VERSION 5.8 ;
BUSBITCHARS "[]" ;
DIVIDERCHAR "/" ;
UNITS
    DATABASE MICRONS 1000 ;
END UNITS

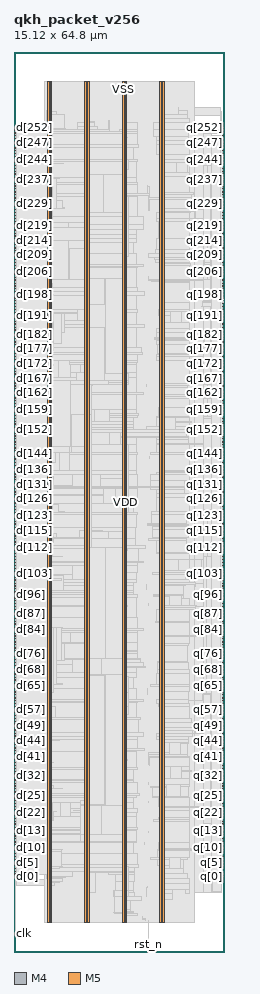
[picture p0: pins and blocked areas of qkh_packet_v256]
MACRO qkh_packet_v256
  FOREIGN qkh_packet_v256 0 0 ;
  CLASS BLOCK ;
  SIZE 15.12 BY 64.8 ;
  PIN clk
    DIRECTION INPUT ;
    USE SIGNAL ;
    PORT
      LAYER M4 ;
        RECT  0.054 1.296 0.138 1.32 ;
    END
    PORT
      LAYER M4 ;
        RECT  0.108 1.296 0.227 1.416 ;
    END
  END clk
  PIN d[0]
    DIRECTION INPUT ;
    USE SIGNAL ;
    PORT
      LAYER M4 ;
        RECT  0.054 5.424 0.138 5.448 ;
    END
  END d[0]
  PIN d[100]
    DIRECTION INPUT ;
    USE SIGNAL ;
    PORT
      LAYER M4 ;
        RECT  0.054 26.544 0.138 26.568 ;
    END
  END d[100]
  PIN d[101]
    DIRECTION INPUT ;
    USE SIGNAL ;
    PORT
      LAYER M4 ;
        RECT  0.054 26.784 0.138 26.808 ;
    END
  END d[101]
  PIN d[102]
    DIRECTION INPUT ;
    USE SIGNAL ;
    PORT
      LAYER M4 ;
        RECT  0.054 26.976 0.138 27 ;
    END
  END d[102]
  PIN d[103]
    DIRECTION INPUT ;
    USE SIGNAL ;
    PORT
      LAYER M4 ;
        RECT  0.054 27.216 0.138 27.24 ;
    END
  END d[103]
  PIN d[104]
    DIRECTION INPUT ;
    USE SIGNAL ;
    PORT
      LAYER M4 ;
        RECT  0.054 27.408 0.138 27.432 ;
    END
  END d[104]
  PIN d[105]
    DIRECTION INPUT ;
    USE SIGNAL ;
    PORT
      LAYER M4 ;
        RECT  0.054 27.6 0.138 27.624 ;
    END
  END d[105]
  PIN d[106]
    DIRECTION INPUT ;
    USE SIGNAL ;
    PORT
      LAYER M4 ;
        RECT  0.054 27.84 0.138 27.864 ;
    END
  END d[106]
  PIN d[107]
    DIRECTION INPUT ;
    USE SIGNAL ;
    PORT
      LAYER M4 ;
        RECT  0.054 28.032 0.138 28.056 ;
    END
  END d[107]
  PIN d[108]
    DIRECTION INPUT ;
    USE SIGNAL ;
    PORT
      LAYER M4 ;
        RECT  0.054 28.272 0.138 28.296 ;
    END
  END d[108]
  PIN d[109]
    DIRECTION INPUT ;
    USE SIGNAL ;
    PORT
      LAYER M4 ;
        RECT  0.054 28.464 0.138 28.488 ;
    END
  END d[109]
  PIN d[10]
    DIRECTION INPUT ;
    USE SIGNAL ;
    PORT
      LAYER M4 ;
        RECT  0.054 7.488 0.138 7.512 ;
    END
  END d[10]
  PIN d[110]
    DIRECTION INPUT ;
    USE SIGNAL ;
    PORT
      LAYER M4 ;
        RECT  0.054 28.704 0.138 28.728 ;
    END
  END d[110]
  PIN d[111]
    DIRECTION INPUT ;
    USE SIGNAL ;
    PORT
      LAYER M4 ;
        RECT  0.054 28.896 0.138 28.92 ;
    END
  END d[111]
  PIN d[112]
    DIRECTION INPUT ;
    USE SIGNAL ;
    PORT
      LAYER M4 ;
        RECT  0.054 29.088 0.138 29.112 ;
    END
  END d[112]
  PIN d[113]
    DIRECTION INPUT ;
    USE SIGNAL ;
    PORT
      LAYER M4 ;
        RECT  0.054 29.328 0.138 29.352 ;
    END
  END d[113]
  PIN d[114]
    DIRECTION INPUT ;
    USE SIGNAL ;
    PORT
      LAYER M4 ;
        RECT  0.054 29.52 0.138 29.544 ;
    END
  END d[114]
  PIN d[115]
    DIRECTION INPUT ;
    USE SIGNAL ;
    PORT
      LAYER M4 ;
        RECT  0.054 29.76 0.138 29.784 ;
    END
  END d[115]
  PIN d[116]
    DIRECTION INPUT ;
    USE SIGNAL ;
    PORT
      LAYER M4 ;
        RECT  0.054 29.952 0.138 29.976 ;
    END
  END d[116]
  PIN d[117]
    DIRECTION INPUT ;
    USE SIGNAL ;
    PORT
      LAYER M4 ;
        RECT  0.054 30.144 0.138 30.168 ;
    END
  END d[117]
  PIN d[118]
    DIRECTION INPUT ;
    USE SIGNAL ;
    PORT
      LAYER M4 ;
        RECT  0.054 30.384 0.138 30.408 ;
    END
  END d[118]
  PIN d[119]
    DIRECTION INPUT ;
    USE SIGNAL ;
    PORT
      LAYER M4 ;
        RECT  0.054 30.576 0.138 30.6 ;
    END
  END d[119]
  PIN d[11]
    DIRECTION INPUT ;
    USE SIGNAL ;
    PORT
      LAYER M4 ;
        RECT  0.054 7.728 0.138 7.752 ;
    END
  END d[11]
  PIN d[120]
    DIRECTION INPUT ;
    USE SIGNAL ;
    PORT
      LAYER M4 ;
        RECT  0.054 30.816 0.138 30.84 ;
    END
  END d[120]
  PIN d[121]
    DIRECTION INPUT ;
    USE SIGNAL ;
    PORT
      LAYER M4 ;
        RECT  0.054 31.008 0.138 31.032 ;
    END
  END d[121]
  PIN d[122]
    DIRECTION INPUT ;
    USE SIGNAL ;
    PORT
      LAYER M4 ;
        RECT  0.054 31.2 0.138 31.224 ;
    END
  END d[122]
  PIN d[123]
    DIRECTION INPUT ;
    USE SIGNAL ;
    PORT
      LAYER M4 ;
        RECT  0.054 31.44 0.138 31.464 ;
    END
  END d[123]
  PIN d[124]
    DIRECTION INPUT ;
    USE SIGNAL ;
    PORT
      LAYER M4 ;
        RECT  0.054 31.632 0.138 31.656 ;
    END
  END d[124]
  PIN d[125]
    DIRECTION INPUT ;
    USE SIGNAL ;
    PORT
      LAYER M4 ;
        RECT  0.054 31.872 0.138 31.896 ;
    END
  END d[125]
  PIN d[126]
    DIRECTION INPUT ;
    USE SIGNAL ;
    PORT
      LAYER M4 ;
        RECT  0.054 32.064 0.138 32.088 ;
    END
  END d[126]
  PIN d[127]
    DIRECTION INPUT ;
    USE SIGNAL ;
    PORT
      LAYER M4 ;
        RECT  0.054 32.304 0.138 32.328 ;
    END
  END d[127]
  PIN d[128]
    DIRECTION INPUT ;
    USE SIGNAL ;
    PORT
      LAYER M4 ;
        RECT  0.054 32.496 0.138 32.52 ;
    END
  END d[128]
  PIN d[129]
    DIRECTION INPUT ;
    USE SIGNAL ;
    PORT
      LAYER M4 ;
        RECT  0.054 32.688 0.138 32.712 ;
    END
  END d[129]
  PIN d[12]
    DIRECTION INPUT ;
    USE SIGNAL ;
    PORT
      LAYER M4 ;
        RECT  0.054 7.92 0.138 7.944 ;
    END
  END d[12]
  PIN d[130]
    DIRECTION INPUT ;
    USE SIGNAL ;
    PORT
      LAYER M4 ;
        RECT  0.054 32.928 0.138 32.952 ;
    END
  END d[130]
  PIN d[131]
    DIRECTION INPUT ;
    USE SIGNAL ;
    PORT
      LAYER M4 ;
        RECT  0.054 33.12 0.138 33.144 ;
    END
  END d[131]
  PIN d[132]
    DIRECTION INPUT ;
    USE SIGNAL ;
    PORT
      LAYER M4 ;
        RECT  0.054 33.36 0.138 33.384 ;
    END
  END d[132]
  PIN d[133]
    DIRECTION INPUT ;
    USE SIGNAL ;
    PORT
      LAYER M4 ;
        RECT  0.054 33.552 0.138 33.576 ;
    END
  END d[133]
  PIN d[134]
    DIRECTION INPUT ;
    USE SIGNAL ;
    PORT
      LAYER M4 ;
        RECT  0.054 33.744 0.138 33.768 ;
    END
  END d[134]
  PIN d[135]
    DIRECTION INPUT ;
    USE SIGNAL ;
    PORT
      LAYER M4 ;
        RECT  0.054 33.984 0.138 34.008 ;
    END
  END d[135]
  PIN d[136]
    DIRECTION INPUT ;
    USE SIGNAL ;
    PORT
      LAYER M4 ;
        RECT  0.054 34.176 0.138 34.2 ;
    END
  END d[136]
  PIN d[137]
    DIRECTION INPUT ;
    USE SIGNAL ;
    PORT
      LAYER M4 ;
        RECT  0.054 34.416 0.138 34.44 ;
    END
  END d[137]
  PIN d[138]
    DIRECTION INPUT ;
    USE SIGNAL ;
    PORT
      LAYER M4 ;
        RECT  0.054 34.608 0.138 34.632 ;
    END
  END d[138]
  PIN d[139]
    DIRECTION INPUT ;
    USE SIGNAL ;
    PORT
      LAYER M4 ;
        RECT  0.054 34.8 0.138 34.824 ;
    END
  END d[139]
  PIN d[13]
    DIRECTION INPUT ;
    USE SIGNAL ;
    PORT
      LAYER M4 ;
        RECT  0.054 8.16 0.138 8.184 ;
    END
  END d[13]
  PIN d[140]
    DIRECTION INPUT ;
    USE SIGNAL ;
    PORT
      LAYER M4 ;
        RECT  0.054 35.04 0.138 35.064 ;
    END
  END d[140]
  PIN d[141]
    DIRECTION INPUT ;
    USE SIGNAL ;
    PORT
      LAYER M4 ;
        RECT  0.054 35.232 0.138 35.256 ;
    END
  END d[141]
  PIN d[142]
    DIRECTION INPUT ;
    USE SIGNAL ;
    PORT
      LAYER M4 ;
        RECT  0.054 35.472 0.138 35.496 ;
    END
  END d[142]
  PIN d[143]
    DIRECTION INPUT ;
    USE SIGNAL ;
    PORT
      LAYER M4 ;
        RECT  0.054 35.664 0.138 35.688 ;
    END
  END d[143]
  PIN d[144]
    DIRECTION INPUT ;
    USE SIGNAL ;
    PORT
      LAYER M4 ;
        RECT  0.054 35.904 0.138 35.928 ;
    END
  END d[144]
  PIN d[145]
    DIRECTION INPUT ;
    USE SIGNAL ;
    PORT
      LAYER M4 ;
        RECT  0.054 36.096 0.138 36.12 ;
    END
  END d[145]
  PIN d[146]
    DIRECTION INPUT ;
    USE SIGNAL ;
    PORT
      LAYER M4 ;
        RECT  0.054 36.288 0.138 36.312 ;
    END
  END d[146]
  PIN d[147]
    DIRECTION INPUT ;
    USE SIGNAL ;
    PORT
      LAYER M4 ;
        RECT  0.054 36.528 0.138 36.552 ;
    END
  END d[147]
  PIN d[148]
    DIRECTION INPUT ;
    USE SIGNAL ;
    PORT
      LAYER M4 ;
        RECT  0.054 36.72 0.138 36.744 ;
    END
  END d[148]
  PIN d[149]
    DIRECTION INPUT ;
    USE SIGNAL ;
    PORT
      LAYER M4 ;
        RECT  0.054 36.96 0.138 36.984 ;
    END
  END d[149]
  PIN d[14]
    DIRECTION INPUT ;
    USE SIGNAL ;
    PORT
      LAYER M4 ;
        RECT  0.054 8.352 0.138 8.376 ;
    END
  END d[14]
  PIN d[150]
    DIRECTION INPUT ;
    USE SIGNAL ;
    PORT
      LAYER M4 ;
        RECT  0.054 37.152 0.138 37.176 ;
    END
  END d[150]
  PIN d[151]
    DIRECTION INPUT ;
    USE SIGNAL ;
    PORT
      LAYER M4 ;
        RECT  0.054 37.344 0.138 37.368 ;
    END
  END d[151]
  PIN d[152]
    DIRECTION INPUT ;
    USE SIGNAL ;
    PORT
      LAYER M4 ;
        RECT  0.054 37.584 0.138 37.608 ;
    END
  END d[152]
  PIN d[153]
    DIRECTION INPUT ;
    USE SIGNAL ;
    PORT
      LAYER M4 ;
        RECT  0.054 37.776 0.138 37.8 ;
    END
  END d[153]
  PIN d[154]
    DIRECTION INPUT ;
    USE SIGNAL ;
    PORT
      LAYER M4 ;
        RECT  0.054 38.016 0.138 38.04 ;
    END
  END d[154]
  PIN d[155]
    DIRECTION INPUT ;
    USE SIGNAL ;
    PORT
      LAYER M4 ;
        RECT  0.054 38.208 0.138 38.232 ;
    END
  END d[155]
  PIN d[156]
    DIRECTION INPUT ;
    USE SIGNAL ;
    PORT
      LAYER M4 ;
        RECT  0.054 38.4 0.138 38.424 ;
    END
  END d[156]
  PIN d[157]
    DIRECTION INPUT ;
    USE SIGNAL ;
    PORT
      LAYER M4 ;
        RECT  0.054 38.64 0.138 38.664 ;
    END
  END d[157]
  PIN d[158]
    DIRECTION INPUT ;
    USE SIGNAL ;
    PORT
      LAYER M4 ;
        RECT  0.054 38.832 0.138 38.856 ;
    END
  END d[158]
  PIN d[159]
    DIRECTION INPUT ;
    USE SIGNAL ;
    PORT
      LAYER M4 ;
        RECT  0.054 39.072 0.138 39.096 ;
    END
  END d[159]
  PIN d[15]
    DIRECTION INPUT ;
    USE SIGNAL ;
    PORT
      LAYER M4 ;
        RECT  0.054 8.544 0.138 8.568 ;
    END
  END d[15]
  PIN d[160]
    DIRECTION INPUT ;
    USE SIGNAL ;
    PORT
      LAYER M4 ;
        RECT  0.054 39.264 0.138 39.288 ;
    END
  END d[160]
  PIN d[161]
    DIRECTION INPUT ;
    USE SIGNAL ;
    PORT
      LAYER M4 ;
        RECT  0.054 39.504 0.138 39.528 ;
    END
  END d[161]
  PIN d[162]
    DIRECTION INPUT ;
    USE SIGNAL ;
    PORT
      LAYER M4 ;
        RECT  0.054 39.696 0.138 39.72 ;
    END
  END d[162]
  PIN d[163]
    DIRECTION INPUT ;
    USE SIGNAL ;
    PORT
      LAYER M4 ;
        RECT  0.054 39.888 0.138 39.912 ;
    END
  END d[163]
  PIN d[164]
    DIRECTION INPUT ;
    USE SIGNAL ;
    PORT
      LAYER M4 ;
        RECT  0.054 40.128 0.138 40.152 ;
    END
  END d[164]
  PIN d[165]
    DIRECTION INPUT ;
    USE SIGNAL ;
    PORT
      LAYER M4 ;
        RECT  0.054 40.32 0.138 40.344 ;
    END
  END d[165]
  PIN d[166]
    DIRECTION INPUT ;
    USE SIGNAL ;
    PORT
      LAYER M4 ;
        RECT  0.054 40.56 0.138 40.584 ;
    END
  END d[166]
  PIN d[167]
    DIRECTION INPUT ;
    USE SIGNAL ;
    PORT
      LAYER M4 ;
        RECT  0.054 40.752 0.138 40.776 ;
    END
  END d[167]
  PIN d[168]
    DIRECTION INPUT ;
    USE SIGNAL ;
    PORT
      LAYER M4 ;
        RECT  0.054 40.944 0.138 40.968 ;
    END
  END d[168]
  PIN d[169]
    DIRECTION INPUT ;
    USE SIGNAL ;
    PORT
      LAYER M4 ;
        RECT  0.054 41.184 0.138 41.208 ;
    END
  END d[169]
  PIN d[16]
    DIRECTION INPUT ;
    USE SIGNAL ;
    PORT
      LAYER M4 ;
        RECT  0.054 8.784 0.138 8.808 ;
    END
  END d[16]
  PIN d[170]
    DIRECTION INPUT ;
    USE SIGNAL ;
    PORT
      LAYER M4 ;
        RECT  0.054 41.376 0.138 41.4 ;
    END
  END d[170]
  PIN d[171]
    DIRECTION INPUT ;
    USE SIGNAL ;
    PORT
      LAYER M4 ;
        RECT  0.054 41.616 0.138 41.64 ;
    END
  END d[171]
  PIN d[172]
    DIRECTION INPUT ;
    USE SIGNAL ;
    PORT
      LAYER M4 ;
        RECT  0.054 41.808 0.138 41.832 ;
    END
  END d[172]
  PIN d[173]
    DIRECTION INPUT ;
    USE SIGNAL ;
    PORT
      LAYER M4 ;
        RECT  0.054 42 0.138 42.024 ;
    END
  END d[173]
  PIN d[174]
    DIRECTION INPUT ;
    USE SIGNAL ;
    PORT
      LAYER M4 ;
        RECT  0.054 42.24 0.138 42.264 ;
    END
  END d[174]
  PIN d[175]
    DIRECTION INPUT ;
    USE SIGNAL ;
    PORT
      LAYER M4 ;
        RECT  0.054 42.432 0.138 42.456 ;
    END
  END d[175]
  PIN d[176]
    DIRECTION INPUT ;
    USE SIGNAL ;
    PORT
      LAYER M4 ;
        RECT  0.054 42.672 0.138 42.696 ;
    END
  END d[176]
  PIN d[177]
    DIRECTION INPUT ;
    USE SIGNAL ;
    PORT
      LAYER M4 ;
        RECT  0.054 42.864 0.138 42.888 ;
    END
  END d[177]
  PIN d[178]
    DIRECTION INPUT ;
    USE SIGNAL ;
    PORT
      LAYER M4 ;
        RECT  0.054 43.104 0.138 43.128 ;
    END
  END d[178]
  PIN d[179]
    DIRECTION INPUT ;
    USE SIGNAL ;
    PORT
      LAYER M4 ;
        RECT  0.054 43.296 0.138 43.32 ;
    END
  END d[179]
  PIN d[17]
    DIRECTION INPUT ;
    USE SIGNAL ;
    PORT
      LAYER M4 ;
        RECT  0.054 8.976 0.138 9 ;
    END
  END d[17]
  PIN d[180]
    DIRECTION INPUT ;
    USE SIGNAL ;
    PORT
      LAYER M4 ;
        RECT  0.054 43.488 0.138 43.512 ;
    END
  END d[180]
  PIN d[181]
    DIRECTION INPUT ;
    USE SIGNAL ;
    PORT
      LAYER M4 ;
        RECT  0.054 43.728 0.138 43.752 ;
    END
  END d[181]
  PIN d[182]
    DIRECTION INPUT ;
    USE SIGNAL ;
    PORT
      LAYER M4 ;
        RECT  0.054 43.92 0.138 43.944 ;
    END
  END d[182]
  PIN d[183]
    DIRECTION INPUT ;
    USE SIGNAL ;
    PORT
      LAYER M4 ;
        RECT  0.054 44.16 0.138 44.184 ;
    END
  END d[183]
  PIN d[184]
    DIRECTION INPUT ;
    USE SIGNAL ;
    PORT
      LAYER M4 ;
        RECT  0.054 44.352 0.138 44.376 ;
    END
  END d[184]
  PIN d[185]
    DIRECTION INPUT ;
    USE SIGNAL ;
    PORT
      LAYER M4 ;
        RECT  0.054 44.544 0.138 44.568 ;
    END
  END d[185]
  PIN d[186]
    DIRECTION INPUT ;
    USE SIGNAL ;
    PORT
      LAYER M4 ;
        RECT  0.054 44.784 0.138 44.808 ;
    END
  END d[186]
  PIN d[187]
    DIRECTION INPUT ;
    USE SIGNAL ;
    PORT
      LAYER M4 ;
        RECT  0.054 44.976 0.138 45 ;
    END
  END d[187]
  PIN d[188]
    DIRECTION INPUT ;
    USE SIGNAL ;
    PORT
      LAYER M4 ;
        RECT  0.054 45.216 0.138 45.24 ;
    END
  END d[188]
  PIN d[189]
    DIRECTION INPUT ;
    USE SIGNAL ;
    PORT
      LAYER M4 ;
        RECT  0.054 45.408 0.138 45.432 ;
    END
  END d[189]
  PIN d[18]
    DIRECTION INPUT ;
    USE SIGNAL ;
    PORT
      LAYER M4 ;
        RECT  0.054 9.216 0.138 9.24 ;
    END
  END d[18]
  PIN d[190]
    DIRECTION INPUT ;
    USE SIGNAL ;
    PORT
      LAYER M4 ;
        RECT  0.054 45.6 0.138 45.624 ;
    END
  END d[190]
  PIN d[191]
    DIRECTION INPUT ;
    USE SIGNAL ;
    PORT
      LAYER M4 ;
        RECT  0.054 45.84 0.138 45.864 ;
    END
  END d[191]
  PIN d[192]
    DIRECTION INPUT ;
    USE SIGNAL ;
    PORT
      LAYER M4 ;
        RECT  0.054 46.032 0.138 46.056 ;
    END
  END d[192]
  PIN d[193]
    DIRECTION INPUT ;
    USE SIGNAL ;
    PORT
      LAYER M4 ;
        RECT  0.054 46.272 0.138 46.296 ;
    END
  END d[193]
  PIN d[194]
    DIRECTION INPUT ;
    USE SIGNAL ;
    PORT
      LAYER M4 ;
        RECT  0.054 46.464 0.138 46.488 ;
    END
  END d[194]
  PIN d[195]
    DIRECTION INPUT ;
    USE SIGNAL ;
    PORT
      LAYER M4 ;
        RECT  0.054 46.704 0.138 46.728 ;
    END
  END d[195]
  PIN d[196]
    DIRECTION INPUT ;
    USE SIGNAL ;
    PORT
      LAYER M4 ;
        RECT  0.054 46.896 0.138 46.92 ;
    END
  END d[196]
  PIN d[197]
    DIRECTION INPUT ;
    USE SIGNAL ;
    PORT
      LAYER M4 ;
        RECT  0.054 47.088 0.138 47.112 ;
    END
  END d[197]
  PIN d[198]
    DIRECTION INPUT ;
    USE SIGNAL ;
    PORT
      LAYER M4 ;
        RECT  0.054 47.328 0.138 47.352 ;
    END
  END d[198]
  PIN d[199]
    DIRECTION INPUT ;
    USE SIGNAL ;
    PORT
      LAYER M4 ;
        RECT  0.054 47.52 0.138 47.544 ;
    END
  END d[199]
  PIN d[19]
    DIRECTION INPUT ;
    USE SIGNAL ;
    PORT
      LAYER M4 ;
        RECT  0.054 9.408 0.138 9.432 ;
    END
  END d[19]
  PIN d[1]
    DIRECTION INPUT ;
    USE SIGNAL ;
    PORT
      LAYER M4 ;
        RECT  0.054 5.616 0.138 5.64 ;
    END
  END d[1]
  PIN d[200]
    DIRECTION INPUT ;
    USE SIGNAL ;
    PORT
      LAYER M4 ;
        RECT  0.054 47.76 0.138 47.784 ;
    END
  END d[200]
  PIN d[201]
    DIRECTION INPUT ;
    USE SIGNAL ;
    PORT
      LAYER M4 ;
        RECT  0.054 47.952 0.138 47.976 ;
    END
  END d[201]
  PIN d[202]
    DIRECTION INPUT ;
    USE SIGNAL ;
    PORT
      LAYER M4 ;
        RECT  0.054 48.144 0.138 48.168 ;
    END
  END d[202]
  PIN d[203]
    DIRECTION INPUT ;
    USE SIGNAL ;
    PORT
      LAYER M4 ;
        RECT  0.054 48.384 0.138 48.408 ;
    END
  END d[203]
  PIN d[204]
    DIRECTION INPUT ;
    USE SIGNAL ;
    PORT
      LAYER M4 ;
        RECT  0.054 48.576 0.138 48.6 ;
    END
  END d[204]
  PIN d[205]
    DIRECTION INPUT ;
    USE SIGNAL ;
    PORT
      LAYER M4 ;
        RECT  0.054 48.816 0.138 48.84 ;
    END
  END d[205]
  PIN d[206]
    DIRECTION INPUT ;
    USE SIGNAL ;
    PORT
      LAYER M4 ;
        RECT  0.054 49.008 0.138 49.032 ;
    END
  END d[206]
  PIN d[207]
    DIRECTION INPUT ;
    USE SIGNAL ;
    PORT
      LAYER M4 ;
        RECT  0.054 49.2 0.138 49.224 ;
    END
  END d[207]
  PIN d[208]
    DIRECTION INPUT ;
    USE SIGNAL ;
    PORT
      LAYER M4 ;
        RECT  0.054 49.44 0.138 49.464 ;
    END
  END d[208]
  PIN d[209]
    DIRECTION INPUT ;
    USE SIGNAL ;
    PORT
      LAYER M4 ;
        RECT  0.054 49.632 0.138 49.656 ;
    END
  END d[209]
  PIN d[20]
    DIRECTION INPUT ;
    USE SIGNAL ;
    PORT
      LAYER M4 ;
        RECT  0.054 9.6 0.138 9.624 ;
    END
  END d[20]
  PIN d[210]
    DIRECTION INPUT ;
    USE SIGNAL ;
    PORT
      LAYER M4 ;
        RECT  0.054 49.872 0.138 49.896 ;
    END
  END d[210]
  PIN d[211]
    DIRECTION INPUT ;
    USE SIGNAL ;
    PORT
      LAYER M4 ;
        RECT  0.054 50.064 0.138 50.088 ;
    END
  END d[211]
  PIN d[212]
    DIRECTION INPUT ;
    USE SIGNAL ;
    PORT
      LAYER M4 ;
        RECT  0.054 50.304 0.138 50.328 ;
    END
  END d[212]
  PIN d[213]
    DIRECTION INPUT ;
    USE SIGNAL ;
    PORT
      LAYER M4 ;
        RECT  0.054 50.496 0.138 50.52 ;
    END
  END d[213]
  PIN d[214]
    DIRECTION INPUT ;
    USE SIGNAL ;
    PORT
      LAYER M4 ;
        RECT  0.054 50.688 0.138 50.712 ;
    END
  END d[214]
  PIN d[215]
    DIRECTION INPUT ;
    USE SIGNAL ;
    PORT
      LAYER M4 ;
        RECT  0.054 50.928 0.138 50.952 ;
    END
  END d[215]
  PIN d[216]
    DIRECTION INPUT ;
    USE SIGNAL ;
    PORT
      LAYER M4 ;
        RECT  0.054 51.12 0.138 51.144 ;
    END
  END d[216]
  PIN d[217]
    DIRECTION INPUT ;
    USE SIGNAL ;
    PORT
      LAYER M4 ;
        RECT  0.054 51.36 0.138 51.384 ;
    END
  END d[217]
  PIN d[218]
    DIRECTION INPUT ;
    USE SIGNAL ;
    PORT
      LAYER M4 ;
        RECT  0.054 51.552 0.138 51.576 ;
    END
  END d[218]
  PIN d[219]
    DIRECTION INPUT ;
    USE SIGNAL ;
    PORT
      LAYER M4 ;
        RECT  0.054 51.744 0.138 51.768 ;
    END
  END d[219]
  PIN d[21]
    DIRECTION INPUT ;
    USE SIGNAL ;
    PORT
      LAYER M4 ;
        RECT  0.054 9.84 0.138 9.864 ;
    END
  END d[21]
  PIN d[220]
    DIRECTION INPUT ;
    USE SIGNAL ;
    PORT
      LAYER M4 ;
        RECT  0.054 51.984 0.138 52.008 ;
    END
  END d[220]
  PIN d[221]
    DIRECTION INPUT ;
    USE SIGNAL ;
    PORT
      LAYER M4 ;
        RECT  0.054 52.176 0.138 52.2 ;
    END
  END d[221]
  PIN d[222]
    DIRECTION INPUT ;
    USE SIGNAL ;
    PORT
      LAYER M4 ;
        RECT  0.054 52.416 0.138 52.44 ;
    END
  END d[222]
  PIN d[223]
    DIRECTION INPUT ;
    USE SIGNAL ;
    PORT
      LAYER M4 ;
        RECT  0.054 52.608 0.138 52.632 ;
    END
  END d[223]
  PIN d[224]
    DIRECTION INPUT ;
    USE SIGNAL ;
    PORT
      LAYER M4 ;
        RECT  0.054 52.8 0.138 52.824 ;
    END
  END d[224]
  PIN d[225]
    DIRECTION INPUT ;
    USE SIGNAL ;
    PORT
      LAYER M4 ;
        RECT  0.054 53.04 0.138 53.064 ;
    END
  END d[225]
  PIN d[226]
    DIRECTION INPUT ;
    USE SIGNAL ;
    PORT
      LAYER M4 ;
        RECT  0.054 53.232 0.138 53.256 ;
    END
  END d[226]
  PIN d[227]
    DIRECTION INPUT ;
    USE SIGNAL ;
    PORT
      LAYER M4 ;
        RECT  0.054 53.472 0.138 53.496 ;
    END
  END d[227]
  PIN d[228]
    DIRECTION INPUT ;
    USE SIGNAL ;
    PORT
      LAYER M4 ;
        RECT  0.054 53.664 0.138 53.688 ;
    END
  END d[228]
  PIN d[229]
    DIRECTION INPUT ;
    USE SIGNAL ;
    PORT
      LAYER M4 ;
        RECT  0.054 53.904 0.138 53.928 ;
    END
  END d[229]
  PIN d[22]
    DIRECTION INPUT ;
    USE SIGNAL ;
    PORT
      LAYER M4 ;
        RECT  0.054 10.032 0.138 10.056 ;
    END
  END d[22]
  PIN d[230]
    DIRECTION INPUT ;
    USE SIGNAL ;
    PORT
      LAYER M4 ;
        RECT  0.054 54.096 0.138 54.12 ;
    END
  END d[230]
  PIN d[231]
    DIRECTION INPUT ;
    USE SIGNAL ;
    PORT
      LAYER M4 ;
        RECT  0.054 54.288 0.138 54.312 ;
    END
  END d[231]
  PIN d[232]
    DIRECTION INPUT ;
    USE SIGNAL ;
    PORT
      LAYER M4 ;
        RECT  0.054 54.528 0.138 54.552 ;
    END
  END d[232]
  PIN d[233]
    DIRECTION INPUT ;
    USE SIGNAL ;
    PORT
      LAYER M4 ;
        RECT  0.054 54.72 0.138 54.744 ;
    END
  END d[233]
  PIN d[234]
    DIRECTION INPUT ;
    USE SIGNAL ;
    PORT
      LAYER M4 ;
        RECT  0.054 54.96 0.138 54.984 ;
    END
  END d[234]
  PIN d[235]
    DIRECTION INPUT ;
    USE SIGNAL ;
    PORT
      LAYER M4 ;
        RECT  0.054 55.152 0.138 55.176 ;
    END
  END d[235]
  PIN d[236]
    DIRECTION INPUT ;
    USE SIGNAL ;
    PORT
      LAYER M4 ;
        RECT  0.054 55.344 0.138 55.368 ;
    END
  END d[236]
  PIN d[237]
    DIRECTION INPUT ;
    USE SIGNAL ;
    PORT
      LAYER M4 ;
        RECT  0.054 55.584 0.138 55.608 ;
    END
  END d[237]
  PIN d[238]
    DIRECTION INPUT ;
    USE SIGNAL ;
    PORT
      LAYER M4 ;
        RECT  0.054 55.776 0.138 55.8 ;
    END
  END d[238]
  PIN d[239]
    DIRECTION INPUT ;
    USE SIGNAL ;
    PORT
      LAYER M4 ;
        RECT  0.054 56.016 0.138 56.04 ;
    END
  END d[239]
  PIN d[23]
    DIRECTION INPUT ;
    USE SIGNAL ;
    PORT
      LAYER M4 ;
        RECT  0.054 10.272 0.138 10.296 ;
    END
  END d[23]
  PIN d[240]
    DIRECTION INPUT ;
    USE SIGNAL ;
    PORT
      LAYER M4 ;
        RECT  0.054 56.208 0.138 56.232 ;
    END
  END d[240]
  PIN d[241]
    DIRECTION INPUT ;
    USE SIGNAL ;
    PORT
      LAYER M4 ;
        RECT  0.054 56.4 0.138 56.424 ;
    END
  END d[241]
  PIN d[242]
    DIRECTION INPUT ;
    USE SIGNAL ;
    PORT
      LAYER M4 ;
        RECT  0.054 56.64 0.138 56.664 ;
    END
  END d[242]
  PIN d[243]
    DIRECTION INPUT ;
    USE SIGNAL ;
    PORT
      LAYER M4 ;
        RECT  0.054 56.832 0.138 56.856 ;
    END
  END d[243]
  PIN d[244]
    DIRECTION INPUT ;
    USE SIGNAL ;
    PORT
      LAYER M4 ;
        RECT  0.054 57.072 0.138 57.096 ;
    END
  END d[244]
  PIN d[245]
    DIRECTION INPUT ;
    USE SIGNAL ;
    PORT
      LAYER M4 ;
        RECT  0.054 57.264 0.138 57.288 ;
    END
  END d[245]
  PIN d[246]
    DIRECTION INPUT ;
    USE SIGNAL ;
    PORT
      LAYER M4 ;
        RECT  0.054 57.504 0.138 57.528 ;
    END
  END d[246]
  PIN d[247]
    DIRECTION INPUT ;
    USE SIGNAL ;
    PORT
      LAYER M4 ;
        RECT  0.054 57.696 0.138 57.72 ;
    END
  END d[247]
  PIN d[248]
    DIRECTION INPUT ;
    USE SIGNAL ;
    PORT
      LAYER M4 ;
        RECT  0.054 57.888 0.138 57.912 ;
    END
  END d[248]
  PIN d[249]
    DIRECTION INPUT ;
    USE SIGNAL ;
    PORT
      LAYER M4 ;
        RECT  0.054 58.128 0.138 58.152 ;
    END
  END d[249]
  PIN d[24]
    DIRECTION INPUT ;
    USE SIGNAL ;
    PORT
      LAYER M4 ;
        RECT  0.054 10.464 0.138 10.488 ;
    END
  END d[24]
  PIN d[250]
    DIRECTION INPUT ;
    USE SIGNAL ;
    PORT
      LAYER M4 ;
        RECT  0.054 58.32 0.138 58.344 ;
    END
  END d[250]
  PIN d[251]
    DIRECTION INPUT ;
    USE SIGNAL ;
    PORT
      LAYER M4 ;
        RECT  0.054 58.56 0.138 58.584 ;
    END
  END d[251]
  PIN d[252]
    DIRECTION INPUT ;
    USE SIGNAL ;
    PORT
      LAYER M4 ;
        RECT  0.054 58.752 0.138 58.776 ;
    END
  END d[252]
  PIN d[253]
    DIRECTION INPUT ;
    USE SIGNAL ;
    PORT
      LAYER M4 ;
        RECT  0.054 58.944 0.138 58.968 ;
    END
  END d[253]
  PIN d[254]
    DIRECTION INPUT ;
    USE SIGNAL ;
    PORT
      LAYER M4 ;
        RECT  0.054 59.184 0.138 59.208 ;
    END
  END d[254]
  PIN d[255]
    DIRECTION INPUT ;
    USE SIGNAL ;
    PORT
      LAYER M4 ;
        RECT  0.054 59.376 0.138 59.4 ;
    END
  END d[255]
  PIN d[25]
    DIRECTION INPUT ;
    USE SIGNAL ;
    PORT
      LAYER M4 ;
        RECT  0.054 10.704 0.138 10.728 ;
    END
  END d[25]
  PIN d[26]
    DIRECTION INPUT ;
    USE SIGNAL ;
    PORT
      LAYER M4 ;
        RECT  0.054 10.896 0.138 10.92 ;
    END
  END d[26]
  PIN d[27]
    DIRECTION INPUT ;
    USE SIGNAL ;
    PORT
      LAYER M4 ;
        RECT  0.054 11.088 0.138 11.112 ;
    END
  END d[27]
  PIN d[28]
    DIRECTION INPUT ;
    USE SIGNAL ;
    PORT
      LAYER M4 ;
        RECT  0.054 11.328 0.138 11.352 ;
    END
  END d[28]
  PIN d[29]
    DIRECTION INPUT ;
    USE SIGNAL ;
    PORT
      LAYER M4 ;
        RECT  0.054 11.52 0.138 11.544 ;
    END
  END d[29]
  PIN d[2]
    DIRECTION INPUT ;
    USE SIGNAL ;
    PORT
      LAYER M4 ;
        RECT  0.054 5.808 0.138 5.832 ;
    END
  END d[2]
  PIN d[30]
    DIRECTION INPUT ;
    USE SIGNAL ;
    PORT
      LAYER M4 ;
        RECT  0.054 11.76 0.138 11.784 ;
    END
  END d[30]
  PIN d[31]
    DIRECTION INPUT ;
    USE SIGNAL ;
    PORT
      LAYER M4 ;
        RECT  0.054 11.952 0.138 11.976 ;
    END
  END d[31]
  PIN d[32]
    DIRECTION INPUT ;
    USE SIGNAL ;
    PORT
      LAYER M4 ;
        RECT  0.054 12.144 0.138 12.168 ;
    END
  END d[32]
  PIN d[33]
    DIRECTION INPUT ;
    USE SIGNAL ;
    PORT
      LAYER M4 ;
        RECT  0.054 12.384 0.138 12.408 ;
    END
  END d[33]
  PIN d[34]
    DIRECTION INPUT ;
    USE SIGNAL ;
    PORT
      LAYER M4 ;
        RECT  0.054 12.576 0.138 12.6 ;
    END
  END d[34]
  PIN d[35]
    DIRECTION INPUT ;
    USE SIGNAL ;
    PORT
      LAYER M4 ;
        RECT  0.054 12.816 0.138 12.84 ;
    END
  END d[35]
  PIN d[36]
    DIRECTION INPUT ;
    USE SIGNAL ;
    PORT
      LAYER M4 ;
        RECT  0.054 13.008 0.138 13.032 ;
    END
  END d[36]
  PIN d[37]
    DIRECTION INPUT ;
    USE SIGNAL ;
    PORT
      LAYER M4 ;
        RECT  0.054 13.2 0.138 13.224 ;
    END
  END d[37]
  PIN d[38]
    DIRECTION INPUT ;
    USE SIGNAL ;
    PORT
      LAYER M4 ;
        RECT  0.054 13.44 0.138 13.464 ;
    END
  END d[38]
  PIN d[39]
    DIRECTION INPUT ;
    USE SIGNAL ;
    PORT
      LAYER M4 ;
        RECT  0.054 13.632 0.138 13.656 ;
    END
  END d[39]
  PIN d[3]
    DIRECTION INPUT ;
    USE SIGNAL ;
    PORT
      LAYER M4 ;
        RECT  0.054 6 0.138 6.024 ;
    END
  END d[3]
  PIN d[40]
    DIRECTION INPUT ;
    USE SIGNAL ;
    PORT
      LAYER M4 ;
        RECT  0.054 13.872 0.138 13.896 ;
    END
  END d[40]
  PIN d[41]
    DIRECTION INPUT ;
    USE SIGNAL ;
    PORT
      LAYER M4 ;
        RECT  0.054 14.064 0.138 14.088 ;
    END
  END d[41]
  PIN d[42]
    DIRECTION INPUT ;
    USE SIGNAL ;
    PORT
      LAYER M4 ;
        RECT  0.054 14.304 0.138 14.328 ;
    END
  END d[42]
  PIN d[43]
    DIRECTION INPUT ;
    USE SIGNAL ;
    PORT
      LAYER M4 ;
        RECT  0.054 14.496 0.138 14.52 ;
    END
  END d[43]
  PIN d[44]
    DIRECTION INPUT ;
    USE SIGNAL ;
    PORT
      LAYER M4 ;
        RECT  0.054 14.688 0.138 14.712 ;
    END
  END d[44]
  PIN d[45]
    DIRECTION INPUT ;
    USE SIGNAL ;
    PORT
      LAYER M4 ;
        RECT  0.054 14.928 0.138 14.952 ;
    END
  END d[45]
  PIN d[46]
    DIRECTION INPUT ;
    USE SIGNAL ;
    PORT
      LAYER M4 ;
        RECT  0.054 15.12 0.138 15.144 ;
    END
  END d[46]
  PIN d[47]
    DIRECTION INPUT ;
    USE SIGNAL ;
    PORT
      LAYER M4 ;
        RECT  0.054 15.36 0.138 15.384 ;
    END
  END d[47]
  PIN d[48]
    DIRECTION INPUT ;
    USE SIGNAL ;
    PORT
      LAYER M4 ;
        RECT  0.054 15.552 0.138 15.576 ;
    END
  END d[48]
  PIN d[49]
    DIRECTION INPUT ;
    USE SIGNAL ;
    PORT
      LAYER M4 ;
        RECT  0.054 15.744 0.138 15.768 ;
    END
  END d[49]
  PIN d[4]
    DIRECTION INPUT ;
    USE SIGNAL ;
    PORT
      LAYER M4 ;
        RECT  0.054 6.24 0.138 6.264 ;
    END
  END d[4]
  PIN d[50]
    DIRECTION INPUT ;
    USE SIGNAL ;
    PORT
      LAYER M4 ;
        RECT  0.054 15.984 0.138 16.008 ;
    END
  END d[50]
  PIN d[51]
    DIRECTION INPUT ;
    USE SIGNAL ;
    PORT
      LAYER M4 ;
        RECT  0.054 16.176 0.138 16.2 ;
    END
  END d[51]
  PIN d[52]
    DIRECTION INPUT ;
    USE SIGNAL ;
    PORT
      LAYER M4 ;
        RECT  0.054 16.416 0.138 16.44 ;
    END
  END d[52]
  PIN d[53]
    DIRECTION INPUT ;
    USE SIGNAL ;
    PORT
      LAYER M4 ;
        RECT  0.054 16.608 0.138 16.632 ;
    END
  END d[53]
  PIN d[54]
    DIRECTION INPUT ;
    USE SIGNAL ;
    PORT
      LAYER M4 ;
        RECT  0.054 16.8 0.138 16.824 ;
    END
  END d[54]
  PIN d[55]
    DIRECTION INPUT ;
    USE SIGNAL ;
    PORT
      LAYER M4 ;
        RECT  0.054 17.04 0.138 17.064 ;
    END
  END d[55]
  PIN d[56]
    DIRECTION INPUT ;
    USE SIGNAL ;
    PORT
      LAYER M4 ;
        RECT  0.054 17.232 0.138 17.256 ;
    END
  END d[56]
  PIN d[57]
    DIRECTION INPUT ;
    USE SIGNAL ;
    PORT
      LAYER M4 ;
        RECT  0.054 17.472 0.138 17.496 ;
    END
  END d[57]
  PIN d[58]
    DIRECTION INPUT ;
    USE SIGNAL ;
    PORT
      LAYER M4 ;
        RECT  0.054 17.664 0.138 17.688 ;
    END
  END d[58]
  PIN d[59]
    DIRECTION INPUT ;
    USE SIGNAL ;
    PORT
      LAYER M4 ;
        RECT  0.054 17.904 0.138 17.928 ;
    END
  END d[59]
  PIN d[5]
    DIRECTION INPUT ;
    USE SIGNAL ;
    PORT
      LAYER M4 ;
        RECT  0.054 6.432 0.138 6.456 ;
    END
  END d[5]
  PIN d[60]
    DIRECTION INPUT ;
    USE SIGNAL ;
    PORT
      LAYER M4 ;
        RECT  0.054 18.096 0.138 18.12 ;
    END
  END d[60]
  PIN d[61]
    DIRECTION INPUT ;
    USE SIGNAL ;
    PORT
      LAYER M4 ;
        RECT  0.054 18.288 0.138 18.312 ;
    END
  END d[61]
  PIN d[62]
    DIRECTION INPUT ;
    USE SIGNAL ;
    PORT
      LAYER M4 ;
        RECT  0.054 18.528 0.138 18.552 ;
    END
  END d[62]
  PIN d[63]
    DIRECTION INPUT ;
    USE SIGNAL ;
    PORT
      LAYER M4 ;
        RECT  0.054 18.72 0.138 18.744 ;
    END
  END d[63]
  PIN d[64]
    DIRECTION INPUT ;
    USE SIGNAL ;
    PORT
      LAYER M4 ;
        RECT  0.054 18.96 0.138 18.984 ;
    END
  END d[64]
  PIN d[65]
    DIRECTION INPUT ;
    USE SIGNAL ;
    PORT
      LAYER M4 ;
        RECT  0.054 19.152 0.138 19.176 ;
    END
  END d[65]
  PIN d[66]
    DIRECTION INPUT ;
    USE SIGNAL ;
    PORT
      LAYER M4 ;
        RECT  0.054 19.344 0.138 19.368 ;
    END
  END d[66]
  PIN d[67]
    DIRECTION INPUT ;
    USE SIGNAL ;
    PORT
      LAYER M4 ;
        RECT  0.054 19.584 0.138 19.608 ;
    END
  END d[67]
  PIN d[68]
    DIRECTION INPUT ;
    USE SIGNAL ;
    PORT
      LAYER M4 ;
        RECT  0.054 19.776 0.138 19.8 ;
    END
  END d[68]
  PIN d[69]
    DIRECTION INPUT ;
    USE SIGNAL ;
    PORT
      LAYER M4 ;
        RECT  0.054 20.016 0.138 20.04 ;
    END
  END d[69]
  PIN d[6]
    DIRECTION INPUT ;
    USE SIGNAL ;
    PORT
      LAYER M4 ;
        RECT  0.054 6.672 0.138 6.696 ;
    END
  END d[6]
  PIN d[70]
    DIRECTION INPUT ;
    USE SIGNAL ;
    PORT
      LAYER M4 ;
        RECT  0.054 20.208 0.138 20.232 ;
    END
  END d[70]
  PIN d[71]
    DIRECTION INPUT ;
    USE SIGNAL ;
    PORT
      LAYER M4 ;
        RECT  0.054 20.4 0.138 20.424 ;
    END
  END d[71]
  PIN d[72]
    DIRECTION INPUT ;
    USE SIGNAL ;
    PORT
      LAYER M4 ;
        RECT  0.054 20.64 0.138 20.664 ;
    END
  END d[72]
  PIN d[73]
    DIRECTION INPUT ;
    USE SIGNAL ;
    PORT
      LAYER M4 ;
        RECT  0.054 20.832 0.138 20.856 ;
    END
  END d[73]
  PIN d[74]
    DIRECTION INPUT ;
    USE SIGNAL ;
    PORT
      LAYER M4 ;
        RECT  0.054 21.072 0.138 21.096 ;
    END
  END d[74]
  PIN d[75]
    DIRECTION INPUT ;
    USE SIGNAL ;
    PORT
      LAYER M4 ;
        RECT  0.054 21.264 0.138 21.288 ;
    END
  END d[75]
  PIN d[76]
    DIRECTION INPUT ;
    USE SIGNAL ;
    PORT
      LAYER M4 ;
        RECT  0.054 21.504 0.138 21.528 ;
    END
  END d[76]
  PIN d[77]
    DIRECTION INPUT ;
    USE SIGNAL ;
    PORT
      LAYER M4 ;
        RECT  0.054 21.696 0.138 21.72 ;
    END
  END d[77]
  PIN d[78]
    DIRECTION INPUT ;
    USE SIGNAL ;
    PORT
      LAYER M4 ;
        RECT  0.054 21.888 0.138 21.912 ;
    END
  END d[78]
  PIN d[79]
    DIRECTION INPUT ;
    USE SIGNAL ;
    PORT
      LAYER M4 ;
        RECT  0.054 22.128 0.138 22.152 ;
    END
  END d[79]
  PIN d[7]
    DIRECTION INPUT ;
    USE SIGNAL ;
    PORT
      LAYER M4 ;
        RECT  0.054 6.864 0.138 6.888 ;
    END
  END d[7]
  PIN d[80]
    DIRECTION INPUT ;
    USE SIGNAL ;
    PORT
      LAYER M4 ;
        RECT  0.054 22.32 0.138 22.344 ;
    END
  END d[80]
  PIN d[81]
    DIRECTION INPUT ;
    USE SIGNAL ;
    PORT
      LAYER M4 ;
        RECT  0.054 22.56 0.138 22.584 ;
    END
  END d[81]
  PIN d[82]
    DIRECTION INPUT ;
    USE SIGNAL ;
    PORT
      LAYER M4 ;
        RECT  0.054 22.752 0.138 22.776 ;
    END
  END d[82]
  PIN d[83]
    DIRECTION INPUT ;
    USE SIGNAL ;
    PORT
      LAYER M4 ;
        RECT  0.054 22.944 0.138 22.968 ;
    END
  END d[83]
  PIN d[84]
    DIRECTION INPUT ;
    USE SIGNAL ;
    PORT
      LAYER M4 ;
        RECT  0.054 23.184 0.138 23.208 ;
    END
  END d[84]
  PIN d[85]
    DIRECTION INPUT ;
    USE SIGNAL ;
    PORT
      LAYER M4 ;
        RECT  0.054 23.376 0.138 23.4 ;
    END
  END d[85]
  PIN d[86]
    DIRECTION INPUT ;
    USE SIGNAL ;
    PORT
      LAYER M4 ;
        RECT  0.054 23.616 0.138 23.64 ;
    END
  END d[86]
  PIN d[87]
    DIRECTION INPUT ;
    USE SIGNAL ;
    PORT
      LAYER M4 ;
        RECT  0.054 23.808 0.138 23.832 ;
    END
  END d[87]
  PIN d[88]
    DIRECTION INPUT ;
    USE SIGNAL ;
    PORT
      LAYER M4 ;
        RECT  0.054 24 0.138 24.024 ;
    END
  END d[88]
  PIN d[89]
    DIRECTION INPUT ;
    USE SIGNAL ;
    PORT
      LAYER M4 ;
        RECT  0.054 24.24 0.138 24.264 ;
    END
  END d[89]
  PIN d[8]
    DIRECTION INPUT ;
    USE SIGNAL ;
    PORT
      LAYER M4 ;
        RECT  0.054 7.104 0.138 7.128 ;
    END
  END d[8]
  PIN d[90]
    DIRECTION INPUT ;
    USE SIGNAL ;
    PORT
      LAYER M4 ;
        RECT  0.054 24.432 0.138 24.456 ;
    END
  END d[90]
  PIN d[91]
    DIRECTION INPUT ;
    USE SIGNAL ;
    PORT
      LAYER M4 ;
        RECT  0.054 24.672 0.138 24.696 ;
    END
  END d[91]
  PIN d[92]
    DIRECTION INPUT ;
    USE SIGNAL ;
    PORT
      LAYER M4 ;
        RECT  0.054 24.864 0.138 24.888 ;
    END
  END d[92]
  PIN d[93]
    DIRECTION INPUT ;
    USE SIGNAL ;
    PORT
      LAYER M4 ;
        RECT  0.054 25.104 0.138 25.128 ;
    END
  END d[93]
  PIN d[94]
    DIRECTION INPUT ;
    USE SIGNAL ;
    PORT
      LAYER M4 ;
        RECT  0.054 25.296 0.138 25.32 ;
    END
  END d[94]
  PIN d[95]
    DIRECTION INPUT ;
    USE SIGNAL ;
    PORT
      LAYER M4 ;
        RECT  0.054 25.488 0.138 25.512 ;
    END
  END d[95]
  PIN d[96]
    DIRECTION INPUT ;
    USE SIGNAL ;
    PORT
      LAYER M4 ;
        RECT  0.054 25.728 0.138 25.752 ;
    END
  END d[96]
  PIN d[97]
    DIRECTION INPUT ;
    USE SIGNAL ;
    PORT
      LAYER M4 ;
        RECT  0.054 25.92 0.138 25.944 ;
    END
  END d[97]
  PIN d[98]
    DIRECTION INPUT ;
    USE SIGNAL ;
    PORT
      LAYER M4 ;
        RECT  0.054 26.16 0.138 26.184 ;
    END
  END d[98]
  PIN d[99]
    DIRECTION INPUT ;
    USE SIGNAL ;
    PORT
      LAYER M4 ;
        RECT  0.054 26.352 0.138 26.376 ;
    END
  END d[99]
  PIN d[9]
    DIRECTION INPUT ;
    USE SIGNAL ;
    PORT
      LAYER M4 ;
        RECT  0.054 7.296 0.138 7.32 ;
    END
  END d[9]
  PIN q[0]
    DIRECTION OUTPUT ;
    USE SIGNAL ;
    PORT
      LAYER M4 ;
        RECT  14.982 5.424 15.066 5.448 ;
    END
  END q[0]
  PIN q[100]
    DIRECTION OUTPUT ;
    USE SIGNAL ;
    PORT
      LAYER M4 ;
        RECT  14.982 26.544 15.066 26.568 ;
    END
  END q[100]
  PIN q[101]
    DIRECTION OUTPUT ;
    USE SIGNAL ;
    PORT
      LAYER M4 ;
        RECT  14.982 26.784 15.066 26.808 ;
    END
  END q[101]
  PIN q[102]
    DIRECTION OUTPUT ;
    USE SIGNAL ;
    PORT
      LAYER M4 ;
        RECT  14.982 26.976 15.066 27 ;
    END
  END q[102]
  PIN q[103]
    DIRECTION OUTPUT ;
    USE SIGNAL ;
    PORT
      LAYER M4 ;
        RECT  14.982 27.216 15.066 27.24 ;
    END
  END q[103]
  PIN q[104]
    DIRECTION OUTPUT ;
    USE SIGNAL ;
    PORT
      LAYER M4 ;
        RECT  14.982 27.408 15.066 27.432 ;
    END
  END q[104]
  PIN q[105]
    DIRECTION OUTPUT ;
    USE SIGNAL ;
    PORT
      LAYER M4 ;
        RECT  14.982 27.6 15.066 27.624 ;
    END
  END q[105]
  PIN q[106]
    DIRECTION OUTPUT ;
    USE SIGNAL ;
    PORT
      LAYER M4 ;
        RECT  14.982 27.84 15.066 27.864 ;
    END
  END q[106]
  PIN q[107]
    DIRECTION OUTPUT ;
    USE SIGNAL ;
    PORT
      LAYER M4 ;
        RECT  14.982 28.032 15.066 28.056 ;
    END
  END q[107]
  PIN q[108]
    DIRECTION OUTPUT ;
    USE SIGNAL ;
    PORT
      LAYER M4 ;
        RECT  14.982 28.272 15.066 28.296 ;
    END
  END q[108]
  PIN q[109]
    DIRECTION OUTPUT ;
    USE SIGNAL ;
    PORT
      LAYER M4 ;
        RECT  14.982 28.464 15.066 28.488 ;
    END
  END q[109]
  PIN q[10]
    DIRECTION OUTPUT ;
    USE SIGNAL ;
    PORT
      LAYER M4 ;
        RECT  14.982 7.488 15.066 7.512 ;
    END
  END q[10]
  PIN q[110]
    DIRECTION OUTPUT ;
    USE SIGNAL ;
    PORT
      LAYER M4 ;
        RECT  14.982 28.704 15.066 28.728 ;
    END
  END q[110]
  PIN q[111]
    DIRECTION OUTPUT ;
    USE SIGNAL ;
    PORT
      LAYER M4 ;
        RECT  14.982 28.896 15.066 28.92 ;
    END
  END q[111]
  PIN q[112]
    DIRECTION OUTPUT ;
    USE SIGNAL ;
    PORT
      LAYER M4 ;
        RECT  14.982 29.088 15.066 29.112 ;
    END
  END q[112]
  PIN q[113]
    DIRECTION OUTPUT ;
    USE SIGNAL ;
    PORT
      LAYER M4 ;
        RECT  14.982 29.328 15.066 29.352 ;
    END
  END q[113]
  PIN q[114]
    DIRECTION OUTPUT ;
    USE SIGNAL ;
    PORT
      LAYER M4 ;
        RECT  14.982 29.52 15.066 29.544 ;
    END
  END q[114]
  PIN q[115]
    DIRECTION OUTPUT ;
    USE SIGNAL ;
    PORT
      LAYER M4 ;
        RECT  14.982 29.76 15.066 29.784 ;
    END
  END q[115]
  PIN q[116]
    DIRECTION OUTPUT ;
    USE SIGNAL ;
    PORT
      LAYER M4 ;
        RECT  14.982 29.952 15.066 29.976 ;
    END
  END q[116]
  PIN q[117]
    DIRECTION OUTPUT ;
    USE SIGNAL ;
    PORT
      LAYER M4 ;
        RECT  14.982 30.144 15.066 30.168 ;
    END
  END q[117]
  PIN q[118]
    DIRECTION OUTPUT ;
    USE SIGNAL ;
    PORT
      LAYER M4 ;
        RECT  14.982 30.384 15.066 30.408 ;
    END
  END q[118]
  PIN q[119]
    DIRECTION OUTPUT ;
    USE SIGNAL ;
    PORT
      LAYER M4 ;
        RECT  14.982 30.576 15.066 30.6 ;
    END
  END q[119]
  PIN q[11]
    DIRECTION OUTPUT ;
    USE SIGNAL ;
    PORT
      LAYER M4 ;
        RECT  14.982 7.728 15.066 7.752 ;
    END
  END q[11]
  PIN q[120]
    DIRECTION OUTPUT ;
    USE SIGNAL ;
    PORT
      LAYER M4 ;
        RECT  14.982 30.816 15.066 30.84 ;
    END
  END q[120]
  PIN q[121]
    DIRECTION OUTPUT ;
    USE SIGNAL ;
    PORT
      LAYER M4 ;
        RECT  14.982 31.008 15.066 31.032 ;
    END
  END q[121]
  PIN q[122]
    DIRECTION OUTPUT ;
    USE SIGNAL ;
    PORT
      LAYER M4 ;
        RECT  14.982 31.2 15.066 31.224 ;
    END
  END q[122]
  PIN q[123]
    DIRECTION OUTPUT ;
    USE SIGNAL ;
    PORT
      LAYER M4 ;
        RECT  14.982 31.44 15.066 31.464 ;
    END
  END q[123]
  PIN q[124]
    DIRECTION OUTPUT ;
    USE SIGNAL ;
    PORT
      LAYER M4 ;
        RECT  14.982 31.632 15.066 31.656 ;
    END
  END q[124]
  PIN q[125]
    DIRECTION OUTPUT ;
    USE SIGNAL ;
    PORT
      LAYER M4 ;
        RECT  14.982 31.872 15.066 31.896 ;
    END
  END q[125]
  PIN q[126]
    DIRECTION OUTPUT ;
    USE SIGNAL ;
    PORT
      LAYER M4 ;
        RECT  14.982 32.064 15.066 32.088 ;
    END
  END q[126]
  PIN q[127]
    DIRECTION OUTPUT ;
    USE SIGNAL ;
    PORT
      LAYER M4 ;
        RECT  14.982 32.304 15.066 32.328 ;
    END
  END q[127]
  PIN q[128]
    DIRECTION OUTPUT ;
    USE SIGNAL ;
    PORT
      LAYER M4 ;
        RECT  14.982 32.496 15.066 32.52 ;
    END
  END q[128]
  PIN q[129]
    DIRECTION OUTPUT ;
    USE SIGNAL ;
    PORT
      LAYER M4 ;
        RECT  14.982 32.688 15.066 32.712 ;
    END
  END q[129]
  PIN q[12]
    DIRECTION OUTPUT ;
    USE SIGNAL ;
    PORT
      LAYER M4 ;
        RECT  14.982 7.92 15.066 7.944 ;
    END
  END q[12]
  PIN q[130]
    DIRECTION OUTPUT ;
    USE SIGNAL ;
    PORT
      LAYER M4 ;
        RECT  14.982 32.928 15.066 32.952 ;
    END
  END q[130]
  PIN q[131]
    DIRECTION OUTPUT ;
    USE SIGNAL ;
    PORT
      LAYER M4 ;
        RECT  14.982 33.12 15.066 33.144 ;
    END
  END q[131]
  PIN q[132]
    DIRECTION OUTPUT ;
    USE SIGNAL ;
    PORT
      LAYER M4 ;
        RECT  14.982 33.36 15.066 33.384 ;
    END
  END q[132]
  PIN q[133]
    DIRECTION OUTPUT ;
    USE SIGNAL ;
    PORT
      LAYER M4 ;
        RECT  14.982 33.552 15.066 33.576 ;
    END
  END q[133]
  PIN q[134]
    DIRECTION OUTPUT ;
    USE SIGNAL ;
    PORT
      LAYER M4 ;
        RECT  14.982 33.744 15.066 33.768 ;
    END
  END q[134]
  PIN q[135]
    DIRECTION OUTPUT ;
    USE SIGNAL ;
    PORT
      LAYER M4 ;
        RECT  14.982 33.984 15.066 34.008 ;
    END
  END q[135]
  PIN q[136]
    DIRECTION OUTPUT ;
    USE SIGNAL ;
    PORT
      LAYER M4 ;
        RECT  14.982 34.176 15.066 34.2 ;
    END
  END q[136]
  PIN q[137]
    DIRECTION OUTPUT ;
    USE SIGNAL ;
    PORT
      LAYER M4 ;
        RECT  14.982 34.416 15.066 34.44 ;
    END
  END q[137]
  PIN q[138]
    DIRECTION OUTPUT ;
    USE SIGNAL ;
    PORT
      LAYER M4 ;
        RECT  14.982 34.608 15.066 34.632 ;
    END
  END q[138]
  PIN q[139]
    DIRECTION OUTPUT ;
    USE SIGNAL ;
    PORT
      LAYER M4 ;
        RECT  14.982 34.8 15.066 34.824 ;
    END
  END q[139]
  PIN q[13]
    DIRECTION OUTPUT ;
    USE SIGNAL ;
    PORT
      LAYER M4 ;
        RECT  14.982 8.16 15.066 8.184 ;
    END
  END q[13]
  PIN q[140]
    DIRECTION OUTPUT ;
    USE SIGNAL ;
    PORT
      LAYER M4 ;
        RECT  14.982 35.04 15.066 35.064 ;
    END
  END q[140]
  PIN q[141]
    DIRECTION OUTPUT ;
    USE SIGNAL ;
    PORT
      LAYER M4 ;
        RECT  14.982 35.232 15.066 35.256 ;
    END
  END q[141]
  PIN q[142]
    DIRECTION OUTPUT ;
    USE SIGNAL ;
    PORT
      LAYER M4 ;
        RECT  14.982 35.472 15.066 35.496 ;
    END
  END q[142]
  PIN q[143]
    DIRECTION OUTPUT ;
    USE SIGNAL ;
    PORT
      LAYER M4 ;
        RECT  14.982 35.664 15.066 35.688 ;
    END
  END q[143]
  PIN q[144]
    DIRECTION OUTPUT ;
    USE SIGNAL ;
    PORT
      LAYER M4 ;
        RECT  14.982 35.904 15.066 35.928 ;
    END
  END q[144]
  PIN q[145]
    DIRECTION OUTPUT ;
    USE SIGNAL ;
    PORT
      LAYER M4 ;
        RECT  14.982 36.096 15.066 36.12 ;
    END
  END q[145]
  PIN q[146]
    DIRECTION OUTPUT ;
    USE SIGNAL ;
    PORT
      LAYER M4 ;
        RECT  14.982 36.288 15.066 36.312 ;
    END
  END q[146]
  PIN q[147]
    DIRECTION OUTPUT ;
    USE SIGNAL ;
    PORT
      LAYER M4 ;
        RECT  14.982 36.528 15.066 36.552 ;
    END
  END q[147]
  PIN q[148]
    DIRECTION OUTPUT ;
    USE SIGNAL ;
    PORT
      LAYER M4 ;
        RECT  14.982 36.72 15.066 36.744 ;
    END
  END q[148]
  PIN q[149]
    DIRECTION OUTPUT ;
    USE SIGNAL ;
    PORT
      LAYER M4 ;
        RECT  14.982 36.96 15.066 36.984 ;
    END
  END q[149]
  PIN q[14]
    DIRECTION OUTPUT ;
    USE SIGNAL ;
    PORT
      LAYER M4 ;
        RECT  14.982 8.352 15.066 8.376 ;
    END
  END q[14]
  PIN q[150]
    DIRECTION OUTPUT ;
    USE SIGNAL ;
    PORT
      LAYER M4 ;
        RECT  14.982 37.152 15.066 37.176 ;
    END
  END q[150]
  PIN q[151]
    DIRECTION OUTPUT ;
    USE SIGNAL ;
    PORT
      LAYER M4 ;
        RECT  14.982 37.344 15.066 37.368 ;
    END
  END q[151]
  PIN q[152]
    DIRECTION OUTPUT ;
    USE SIGNAL ;
    PORT
      LAYER M4 ;
        RECT  14.982 37.584 15.066 37.608 ;
    END
  END q[152]
  PIN q[153]
    DIRECTION OUTPUT ;
    USE SIGNAL ;
    PORT
      LAYER M4 ;
        RECT  14.982 37.776 15.066 37.8 ;
    END
  END q[153]
  PIN q[154]
    DIRECTION OUTPUT ;
    USE SIGNAL ;
    PORT
      LAYER M4 ;
        RECT  14.982 38.016 15.066 38.04 ;
    END
  END q[154]
  PIN q[155]
    DIRECTION OUTPUT ;
    USE SIGNAL ;
    PORT
      LAYER M4 ;
        RECT  14.982 38.208 15.066 38.232 ;
    END
  END q[155]
  PIN q[156]
    DIRECTION OUTPUT ;
    USE SIGNAL ;
    PORT
      LAYER M4 ;
        RECT  14.982 38.4 15.066 38.424 ;
    END
  END q[156]
  PIN q[157]
    DIRECTION OUTPUT ;
    USE SIGNAL ;
    PORT
      LAYER M4 ;
        RECT  14.982 38.64 15.066 38.664 ;
    END
  END q[157]
  PIN q[158]
    DIRECTION OUTPUT ;
    USE SIGNAL ;
    PORT
      LAYER M4 ;
        RECT  14.982 38.832 15.066 38.856 ;
    END
  END q[158]
  PIN q[159]
    DIRECTION OUTPUT ;
    USE SIGNAL ;
    PORT
      LAYER M4 ;
        RECT  14.982 39.072 15.066 39.096 ;
    END
  END q[159]
  PIN q[15]
    DIRECTION OUTPUT ;
    USE SIGNAL ;
    PORT
      LAYER M4 ;
        RECT  14.982 8.544 15.066 8.568 ;
    END
  END q[15]
  PIN q[160]
    DIRECTION OUTPUT ;
    USE SIGNAL ;
    PORT
      LAYER M4 ;
        RECT  14.982 39.264 15.066 39.288 ;
    END
  END q[160]
  PIN q[161]
    DIRECTION OUTPUT ;
    USE SIGNAL ;
    PORT
      LAYER M4 ;
        RECT  14.982 39.504 15.066 39.528 ;
    END
  END q[161]
  PIN q[162]
    DIRECTION OUTPUT ;
    USE SIGNAL ;
    PORT
      LAYER M4 ;
        RECT  14.982 39.696 15.066 39.72 ;
    END
  END q[162]
  PIN q[163]
    DIRECTION OUTPUT ;
    USE SIGNAL ;
    PORT
      LAYER M4 ;
        RECT  14.982 39.888 15.066 39.912 ;
    END
  END q[163]
  PIN q[164]
    DIRECTION OUTPUT ;
    USE SIGNAL ;
    PORT
      LAYER M4 ;
        RECT  14.982 40.128 15.066 40.152 ;
    END
  END q[164]
  PIN q[165]
    DIRECTION OUTPUT ;
    USE SIGNAL ;
    PORT
      LAYER M4 ;
        RECT  14.982 40.32 15.066 40.344 ;
    END
  END q[165]
  PIN q[166]
    DIRECTION OUTPUT ;
    USE SIGNAL ;
    PORT
      LAYER M4 ;
        RECT  14.982 40.56 15.066 40.584 ;
    END
  END q[166]
  PIN q[167]
    DIRECTION OUTPUT ;
    USE SIGNAL ;
    PORT
      LAYER M4 ;
        RECT  14.982 40.752 15.066 40.776 ;
    END
  END q[167]
  PIN q[168]
    DIRECTION OUTPUT ;
    USE SIGNAL ;
    PORT
      LAYER M4 ;
        RECT  14.982 40.944 15.066 40.968 ;
    END
  END q[168]
  PIN q[169]
    DIRECTION OUTPUT ;
    USE SIGNAL ;
    PORT
      LAYER M4 ;
        RECT  14.982 41.184 15.066 41.208 ;
    END
  END q[169]
  PIN q[16]
    DIRECTION OUTPUT ;
    USE SIGNAL ;
    PORT
      LAYER M4 ;
        RECT  14.982 8.784 15.066 8.808 ;
    END
  END q[16]
  PIN q[170]
    DIRECTION OUTPUT ;
    USE SIGNAL ;
    PORT
      LAYER M4 ;
        RECT  14.982 41.376 15.066 41.4 ;
    END
  END q[170]
  PIN q[171]
    DIRECTION OUTPUT ;
    USE SIGNAL ;
    PORT
      LAYER M4 ;
        RECT  14.982 41.616 15.066 41.64 ;
    END
  END q[171]
  PIN q[172]
    DIRECTION OUTPUT ;
    USE SIGNAL ;
    PORT
      LAYER M4 ;
        RECT  14.982 41.808 15.066 41.832 ;
    END
  END q[172]
  PIN q[173]
    DIRECTION OUTPUT ;
    USE SIGNAL ;
    PORT
      LAYER M4 ;
        RECT  14.982 42 15.066 42.024 ;
    END
  END q[173]
  PIN q[174]
    DIRECTION OUTPUT ;
    USE SIGNAL ;
    PORT
      LAYER M4 ;
        RECT  14.982 42.24 15.066 42.264 ;
    END
  END q[174]
  PIN q[175]
    DIRECTION OUTPUT ;
    USE SIGNAL ;
    PORT
      LAYER M4 ;
        RECT  14.982 42.432 15.066 42.456 ;
    END
  END q[175]
  PIN q[176]
    DIRECTION OUTPUT ;
    USE SIGNAL ;
    PORT
      LAYER M4 ;
        RECT  14.982 42.672 15.066 42.696 ;
    END
  END q[176]
  PIN q[177]
    DIRECTION OUTPUT ;
    USE SIGNAL ;
    PORT
      LAYER M4 ;
        RECT  14.982 42.864 15.066 42.888 ;
    END
  END q[177]
  PIN q[178]
    DIRECTION OUTPUT ;
    USE SIGNAL ;
    PORT
      LAYER M4 ;
        RECT  14.982 43.104 15.066 43.128 ;
    END
  END q[178]
  PIN q[179]
    DIRECTION OUTPUT ;
    USE SIGNAL ;
    PORT
      LAYER M4 ;
        RECT  14.982 43.296 15.066 43.32 ;
    END
  END q[179]
  PIN q[17]
    DIRECTION OUTPUT ;
    USE SIGNAL ;
    PORT
      LAYER M4 ;
        RECT  14.982 8.976 15.066 9 ;
    END
  END q[17]
  PIN q[180]
    DIRECTION OUTPUT ;
    USE SIGNAL ;
    PORT
      LAYER M4 ;
        RECT  14.982 43.488 15.066 43.512 ;
    END
  END q[180]
  PIN q[181]
    DIRECTION OUTPUT ;
    USE SIGNAL ;
    PORT
      LAYER M4 ;
        RECT  14.982 43.728 15.066 43.752 ;
    END
  END q[181]
  PIN q[182]
    DIRECTION OUTPUT ;
    USE SIGNAL ;
    PORT
      LAYER M4 ;
        RECT  14.982 43.92 15.066 43.944 ;
    END
  END q[182]
  PIN q[183]
    DIRECTION OUTPUT ;
    USE SIGNAL ;
    PORT
      LAYER M4 ;
        RECT  14.982 44.16 15.066 44.184 ;
    END
  END q[183]
  PIN q[184]
    DIRECTION OUTPUT ;
    USE SIGNAL ;
    PORT
      LAYER M4 ;
        RECT  14.982 44.352 15.066 44.376 ;
    END
  END q[184]
  PIN q[185]
    DIRECTION OUTPUT ;
    USE SIGNAL ;
    PORT
      LAYER M4 ;
        RECT  14.982 44.544 15.066 44.568 ;
    END
  END q[185]
  PIN q[186]
    DIRECTION OUTPUT ;
    USE SIGNAL ;
    PORT
      LAYER M4 ;
        RECT  14.982 44.784 15.066 44.808 ;
    END
  END q[186]
  PIN q[187]
    DIRECTION OUTPUT ;
    USE SIGNAL ;
    PORT
      LAYER M4 ;
        RECT  14.982 44.976 15.066 45 ;
    END
  END q[187]
  PIN q[188]
    DIRECTION OUTPUT ;
    USE SIGNAL ;
    PORT
      LAYER M4 ;
        RECT  14.982 45.216 15.066 45.24 ;
    END
  END q[188]
  PIN q[189]
    DIRECTION OUTPUT ;
    USE SIGNAL ;
    PORT
      LAYER M4 ;
        RECT  14.982 45.408 15.066 45.432 ;
    END
  END q[189]
  PIN q[18]
    DIRECTION OUTPUT ;
    USE SIGNAL ;
    PORT
      LAYER M4 ;
        RECT  14.982 9.216 15.066 9.24 ;
    END
  END q[18]
  PIN q[190]
    DIRECTION OUTPUT ;
    USE SIGNAL ;
    PORT
      LAYER M4 ;
        RECT  14.982 45.6 15.066 45.624 ;
    END
  END q[190]
  PIN q[191]
    DIRECTION OUTPUT ;
    USE SIGNAL ;
    PORT
      LAYER M4 ;
        RECT  14.982 45.84 15.066 45.864 ;
    END
  END q[191]
  PIN q[192]
    DIRECTION OUTPUT ;
    USE SIGNAL ;
    PORT
      LAYER M4 ;
        RECT  14.982 46.032 15.066 46.056 ;
    END
  END q[192]
  PIN q[193]
    DIRECTION OUTPUT ;
    USE SIGNAL ;
    PORT
      LAYER M4 ;
        RECT  14.982 46.272 15.066 46.296 ;
    END
  END q[193]
  PIN q[194]
    DIRECTION OUTPUT ;
    USE SIGNAL ;
    PORT
      LAYER M4 ;
        RECT  14.982 46.464 15.066 46.488 ;
    END
  END q[194]
  PIN q[195]
    DIRECTION OUTPUT ;
    USE SIGNAL ;
    PORT
      LAYER M4 ;
        RECT  14.982 46.704 15.066 46.728 ;
    END
  END q[195]
  PIN q[196]
    DIRECTION OUTPUT ;
    USE SIGNAL ;
    PORT
      LAYER M4 ;
        RECT  14.982 46.896 15.066 46.92 ;
    END
  END q[196]
  PIN q[197]
    DIRECTION OUTPUT ;
    USE SIGNAL ;
    PORT
      LAYER M4 ;
        RECT  14.982 47.088 15.066 47.112 ;
    END
  END q[197]
  PIN q[198]
    DIRECTION OUTPUT ;
    USE SIGNAL ;
    PORT
      LAYER M4 ;
        RECT  14.982 47.328 15.066 47.352 ;
    END
  END q[198]
  PIN q[199]
    DIRECTION OUTPUT ;
    USE SIGNAL ;
    PORT
      LAYER M4 ;
        RECT  14.982 47.52 15.066 47.544 ;
    END
  END q[199]
  PIN q[19]
    DIRECTION OUTPUT ;
    USE SIGNAL ;
    PORT
      LAYER M4 ;
        RECT  14.982 9.408 15.066 9.432 ;
    END
  END q[19]
  PIN q[1]
    DIRECTION OUTPUT ;
    USE SIGNAL ;
    PORT
      LAYER M4 ;
        RECT  14.982 5.616 15.066 5.64 ;
    END
  END q[1]
  PIN q[200]
    DIRECTION OUTPUT ;
    USE SIGNAL ;
    PORT
      LAYER M4 ;
        RECT  14.982 47.76 15.066 47.784 ;
    END
  END q[200]
  PIN q[201]
    DIRECTION OUTPUT ;
    USE SIGNAL ;
    PORT
      LAYER M4 ;
        RECT  14.982 47.952 15.066 47.976 ;
    END
  END q[201]
  PIN q[202]
    DIRECTION OUTPUT ;
    USE SIGNAL ;
    PORT
      LAYER M4 ;
        RECT  14.982 48.144 15.066 48.168 ;
    END
  END q[202]
  PIN q[203]
    DIRECTION OUTPUT ;
    USE SIGNAL ;
    PORT
      LAYER M4 ;
        RECT  14.982 48.384 15.066 48.408 ;
    END
  END q[203]
  PIN q[204]
    DIRECTION OUTPUT ;
    USE SIGNAL ;
    PORT
      LAYER M4 ;
        RECT  14.982 48.576 15.066 48.6 ;
    END
  END q[204]
  PIN q[205]
    DIRECTION OUTPUT ;
    USE SIGNAL ;
    PORT
      LAYER M4 ;
        RECT  14.982 48.816 15.066 48.84 ;
    END
  END q[205]
  PIN q[206]
    DIRECTION OUTPUT ;
    USE SIGNAL ;
    PORT
      LAYER M4 ;
        RECT  14.982 49.008 15.066 49.032 ;
    END
  END q[206]
  PIN q[207]
    DIRECTION OUTPUT ;
    USE SIGNAL ;
    PORT
      LAYER M4 ;
        RECT  14.982 49.2 15.066 49.224 ;
    END
  END q[207]
  PIN q[208]
    DIRECTION OUTPUT ;
    USE SIGNAL ;
    PORT
      LAYER M4 ;
        RECT  14.982 49.44 15.066 49.464 ;
    END
  END q[208]
  PIN q[209]
    DIRECTION OUTPUT ;
    USE SIGNAL ;
    PORT
      LAYER M4 ;
        RECT  14.982 49.632 15.066 49.656 ;
    END
  END q[209]
  PIN q[20]
    DIRECTION OUTPUT ;
    USE SIGNAL ;
    PORT
      LAYER M4 ;
        RECT  14.982 9.6 15.066 9.624 ;
    END
  END q[20]
  PIN q[210]
    DIRECTION OUTPUT ;
    USE SIGNAL ;
    PORT
      LAYER M4 ;
        RECT  14.982 49.872 15.066 49.896 ;
    END
  END q[210]
  PIN q[211]
    DIRECTION OUTPUT ;
    USE SIGNAL ;
    PORT
      LAYER M4 ;
        RECT  14.982 50.064 15.066 50.088 ;
    END
  END q[211]
  PIN q[212]
    DIRECTION OUTPUT ;
    USE SIGNAL ;
    PORT
      LAYER M4 ;
        RECT  14.982 50.304 15.066 50.328 ;
    END
  END q[212]
  PIN q[213]
    DIRECTION OUTPUT ;
    USE SIGNAL ;
    PORT
      LAYER M4 ;
        RECT  14.982 50.496 15.066 50.52 ;
    END
  END q[213]
  PIN q[214]
    DIRECTION OUTPUT ;
    USE SIGNAL ;
    PORT
      LAYER M4 ;
        RECT  14.982 50.688 15.066 50.712 ;
    END
  END q[214]
  PIN q[215]
    DIRECTION OUTPUT ;
    USE SIGNAL ;
    PORT
      LAYER M4 ;
        RECT  14.982 50.928 15.066 50.952 ;
    END
  END q[215]
  PIN q[216]
    DIRECTION OUTPUT ;
    USE SIGNAL ;
    PORT
      LAYER M4 ;
        RECT  14.982 51.12 15.066 51.144 ;
    END
  END q[216]
  PIN q[217]
    DIRECTION OUTPUT ;
    USE SIGNAL ;
    PORT
      LAYER M4 ;
        RECT  14.982 51.36 15.066 51.384 ;
    END
  END q[217]
  PIN q[218]
    DIRECTION OUTPUT ;
    USE SIGNAL ;
    PORT
      LAYER M4 ;
        RECT  14.982 51.552 15.066 51.576 ;
    END
  END q[218]
  PIN q[219]
    DIRECTION OUTPUT ;
    USE SIGNAL ;
    PORT
      LAYER M4 ;
        RECT  14.982 51.744 15.066 51.768 ;
    END
  END q[219]
  PIN q[21]
    DIRECTION OUTPUT ;
    USE SIGNAL ;
    PORT
      LAYER M4 ;
        RECT  14.982 9.84 15.066 9.864 ;
    END
  END q[21]
  PIN q[220]
    DIRECTION OUTPUT ;
    USE SIGNAL ;
    PORT
      LAYER M4 ;
        RECT  14.982 51.984 15.066 52.008 ;
    END
  END q[220]
  PIN q[221]
    DIRECTION OUTPUT ;
    USE SIGNAL ;
    PORT
      LAYER M4 ;
        RECT  14.982 52.176 15.066 52.2 ;
    END
  END q[221]
  PIN q[222]
    DIRECTION OUTPUT ;
    USE SIGNAL ;
    PORT
      LAYER M4 ;
        RECT  14.982 52.416 15.066 52.44 ;
    END
  END q[222]
  PIN q[223]
    DIRECTION OUTPUT ;
    USE SIGNAL ;
    PORT
      LAYER M4 ;
        RECT  14.982 52.608 15.066 52.632 ;
    END
  END q[223]
  PIN q[224]
    DIRECTION OUTPUT ;
    USE SIGNAL ;
    PORT
      LAYER M4 ;
        RECT  14.982 52.8 15.066 52.824 ;
    END
  END q[224]
  PIN q[225]
    DIRECTION OUTPUT ;
    USE SIGNAL ;
    PORT
      LAYER M4 ;
        RECT  14.982 53.04 15.066 53.064 ;
    END
  END q[225]
  PIN q[226]
    DIRECTION OUTPUT ;
    USE SIGNAL ;
    PORT
      LAYER M4 ;
        RECT  14.982 53.232 15.066 53.256 ;
    END
  END q[226]
  PIN q[227]
    DIRECTION OUTPUT ;
    USE SIGNAL ;
    PORT
      LAYER M4 ;
        RECT  14.982 53.472 15.066 53.496 ;
    END
  END q[227]
  PIN q[228]
    DIRECTION OUTPUT ;
    USE SIGNAL ;
    PORT
      LAYER M4 ;
        RECT  14.982 53.664 15.066 53.688 ;
    END
  END q[228]
  PIN q[229]
    DIRECTION OUTPUT ;
    USE SIGNAL ;
    PORT
      LAYER M4 ;
        RECT  14.982 53.904 15.066 53.928 ;
    END
  END q[229]
  PIN q[22]
    DIRECTION OUTPUT ;
    USE SIGNAL ;
    PORT
      LAYER M4 ;
        RECT  14.982 10.032 15.066 10.056 ;
    END
  END q[22]
  PIN q[230]
    DIRECTION OUTPUT ;
    USE SIGNAL ;
    PORT
      LAYER M4 ;
        RECT  14.982 54.096 15.066 54.12 ;
    END
  END q[230]
  PIN q[231]
    DIRECTION OUTPUT ;
    USE SIGNAL ;
    PORT
      LAYER M4 ;
        RECT  14.982 54.288 15.066 54.312 ;
    END
  END q[231]
  PIN q[232]
    DIRECTION OUTPUT ;
    USE SIGNAL ;
    PORT
      LAYER M4 ;
        RECT  14.982 54.528 15.066 54.552 ;
    END
  END q[232]
  PIN q[233]
    DIRECTION OUTPUT ;
    USE SIGNAL ;
    PORT
      LAYER M4 ;
        RECT  14.982 54.72 15.066 54.744 ;
    END
  END q[233]
  PIN q[234]
    DIRECTION OUTPUT ;
    USE SIGNAL ;
    PORT
      LAYER M4 ;
        RECT  14.982 54.96 15.066 54.984 ;
    END
  END q[234]
  PIN q[235]
    DIRECTION OUTPUT ;
    USE SIGNAL ;
    PORT
      LAYER M4 ;
        RECT  14.982 55.152 15.066 55.176 ;
    END
  END q[235]
  PIN q[236]
    DIRECTION OUTPUT ;
    USE SIGNAL ;
    PORT
      LAYER M4 ;
        RECT  14.982 55.344 15.066 55.368 ;
    END
  END q[236]
  PIN q[237]
    DIRECTION OUTPUT ;
    USE SIGNAL ;
    PORT
      LAYER M4 ;
        RECT  14.982 55.584 15.066 55.608 ;
    END
  END q[237]
  PIN q[238]
    DIRECTION OUTPUT ;
    USE SIGNAL ;
    PORT
      LAYER M4 ;
        RECT  14.982 55.776 15.066 55.8 ;
    END
  END q[238]
  PIN q[239]
    DIRECTION OUTPUT ;
    USE SIGNAL ;
    PORT
      LAYER M4 ;
        RECT  14.982 56.016 15.066 56.04 ;
    END
  END q[239]
  PIN q[23]
    DIRECTION OUTPUT ;
    USE SIGNAL ;
    PORT
      LAYER M4 ;
        RECT  14.982 10.272 15.066 10.296 ;
    END
  END q[23]
  PIN q[240]
    DIRECTION OUTPUT ;
    USE SIGNAL ;
    PORT
      LAYER M4 ;
        RECT  14.982 56.208 15.066 56.232 ;
    END
  END q[240]
  PIN q[241]
    DIRECTION OUTPUT ;
    USE SIGNAL ;
    PORT
      LAYER M4 ;
        RECT  14.982 56.4 15.066 56.424 ;
    END
  END q[241]
  PIN q[242]
    DIRECTION OUTPUT ;
    USE SIGNAL ;
    PORT
      LAYER M4 ;
        RECT  14.982 56.64 15.066 56.664 ;
    END
  END q[242]
  PIN q[243]
    DIRECTION OUTPUT ;
    USE SIGNAL ;
    PORT
      LAYER M4 ;
        RECT  14.982 56.832 15.066 56.856 ;
    END
  END q[243]
  PIN q[244]
    DIRECTION OUTPUT ;
    USE SIGNAL ;
    PORT
      LAYER M4 ;
        RECT  14.982 57.072 15.066 57.096 ;
    END
  END q[244]
  PIN q[245]
    DIRECTION OUTPUT ;
    USE SIGNAL ;
    PORT
      LAYER M4 ;
        RECT  14.982 57.264 15.066 57.288 ;
    END
  END q[245]
  PIN q[246]
    DIRECTION OUTPUT ;
    USE SIGNAL ;
    PORT
      LAYER M4 ;
        RECT  14.982 57.504 15.066 57.528 ;
    END
  END q[246]
  PIN q[247]
    DIRECTION OUTPUT ;
    USE SIGNAL ;
    PORT
      LAYER M4 ;
        RECT  14.982 57.696 15.066 57.72 ;
    END
  END q[247]
  PIN q[248]
    DIRECTION OUTPUT ;
    USE SIGNAL ;
    PORT
      LAYER M4 ;
        RECT  14.982 57.888 15.066 57.912 ;
    END
  END q[248]
  PIN q[249]
    DIRECTION OUTPUT ;
    USE SIGNAL ;
    PORT
      LAYER M4 ;
        RECT  14.982 58.128 15.066 58.152 ;
    END
  END q[249]
  PIN q[24]
    DIRECTION OUTPUT ;
    USE SIGNAL ;
    PORT
      LAYER M4 ;
        RECT  14.982 10.464 15.066 10.488 ;
    END
  END q[24]
  PIN q[250]
    DIRECTION OUTPUT ;
    USE SIGNAL ;
    PORT
      LAYER M4 ;
        RECT  14.982 58.32 15.066 58.344 ;
    END
  END q[250]
  PIN q[251]
    DIRECTION OUTPUT ;
    USE SIGNAL ;
    PORT
      LAYER M4 ;
        RECT  14.982 58.56 15.066 58.584 ;
    END
  END q[251]
  PIN q[252]
    DIRECTION OUTPUT ;
    USE SIGNAL ;
    PORT
      LAYER M4 ;
        RECT  14.982 58.752 15.066 58.776 ;
    END
  END q[252]
  PIN q[253]
    DIRECTION OUTPUT ;
    USE SIGNAL ;
    PORT
      LAYER M4 ;
        RECT  14.982 58.944 15.066 58.968 ;
    END
  END q[253]
  PIN q[254]
    DIRECTION OUTPUT ;
    USE SIGNAL ;
    PORT
      LAYER M4 ;
        RECT  14.982 59.184 15.066 59.208 ;
    END
  END q[254]
  PIN q[255]
    DIRECTION OUTPUT ;
    USE SIGNAL ;
    PORT
      LAYER M4 ;
        RECT  14.982 59.376 15.066 59.4 ;
    END
  END q[255]
  PIN q[25]
    DIRECTION OUTPUT ;
    USE SIGNAL ;
    PORT
      LAYER M4 ;
        RECT  14.982 10.704 15.066 10.728 ;
    END
  END q[25]
  PIN q[26]
    DIRECTION OUTPUT ;
    USE SIGNAL ;
    PORT
      LAYER M4 ;
        RECT  14.982 10.896 15.066 10.92 ;
    END
  END q[26]
  PIN q[27]
    DIRECTION OUTPUT ;
    USE SIGNAL ;
    PORT
      LAYER M4 ;
        RECT  14.982 11.088 15.066 11.112 ;
    END
  END q[27]
  PIN q[28]
    DIRECTION OUTPUT ;
    USE SIGNAL ;
    PORT
      LAYER M4 ;
        RECT  14.982 11.328 15.066 11.352 ;
    END
  END q[28]
  PIN q[29]
    DIRECTION OUTPUT ;
    USE SIGNAL ;
    PORT
      LAYER M4 ;
        RECT  14.982 11.52 15.066 11.544 ;
    END
  END q[29]
  PIN q[2]
    DIRECTION OUTPUT ;
    USE SIGNAL ;
    PORT
      LAYER M4 ;
        RECT  14.982 5.808 15.066 5.832 ;
    END
  END q[2]
  PIN q[30]
    DIRECTION OUTPUT ;
    USE SIGNAL ;
    PORT
      LAYER M4 ;
        RECT  14.982 11.76 15.066 11.784 ;
    END
  END q[30]
  PIN q[31]
    DIRECTION OUTPUT ;
    USE SIGNAL ;
    PORT
      LAYER M4 ;
        RECT  14.982 11.952 15.066 11.976 ;
    END
  END q[31]
  PIN q[32]
    DIRECTION OUTPUT ;
    USE SIGNAL ;
    PORT
      LAYER M4 ;
        RECT  14.982 12.144 15.066 12.168 ;
    END
  END q[32]
  PIN q[33]
    DIRECTION OUTPUT ;
    USE SIGNAL ;
    PORT
      LAYER M4 ;
        RECT  14.982 12.384 15.066 12.408 ;
    END
  END q[33]
  PIN q[34]
    DIRECTION OUTPUT ;
    USE SIGNAL ;
    PORT
      LAYER M4 ;
        RECT  14.982 12.576 15.066 12.6 ;
    END
  END q[34]
  PIN q[35]
    DIRECTION OUTPUT ;
    USE SIGNAL ;
    PORT
      LAYER M4 ;
        RECT  14.982 12.816 15.066 12.84 ;
    END
  END q[35]
  PIN q[36]
    DIRECTION OUTPUT ;
    USE SIGNAL ;
    PORT
      LAYER M4 ;
        RECT  14.982 13.008 15.066 13.032 ;
    END
  END q[36]
  PIN q[37]
    DIRECTION OUTPUT ;
    USE SIGNAL ;
    PORT
      LAYER M4 ;
        RECT  14.982 13.2 15.066 13.224 ;
    END
  END q[37]
  PIN q[38]
    DIRECTION OUTPUT ;
    USE SIGNAL ;
    PORT
      LAYER M4 ;
        RECT  14.982 13.44 15.066 13.464 ;
    END
  END q[38]
  PIN q[39]
    DIRECTION OUTPUT ;
    USE SIGNAL ;
    PORT
      LAYER M4 ;
        RECT  14.982 13.632 15.066 13.656 ;
    END
  END q[39]
  PIN q[3]
    DIRECTION OUTPUT ;
    USE SIGNAL ;
    PORT
      LAYER M4 ;
        RECT  14.982 6 15.066 6.024 ;
    END
  END q[3]
  PIN q[40]
    DIRECTION OUTPUT ;
    USE SIGNAL ;
    PORT
      LAYER M4 ;
        RECT  14.982 13.872 15.066 13.896 ;
    END
  END q[40]
  PIN q[41]
    DIRECTION OUTPUT ;
    USE SIGNAL ;
    PORT
      LAYER M4 ;
        RECT  14.982 14.064 15.066 14.088 ;
    END
  END q[41]
  PIN q[42]
    DIRECTION OUTPUT ;
    USE SIGNAL ;
    PORT
      LAYER M4 ;
        RECT  14.982 14.304 15.066 14.328 ;
    END
  END q[42]
  PIN q[43]
    DIRECTION OUTPUT ;
    USE SIGNAL ;
    PORT
      LAYER M4 ;
        RECT  14.982 14.496 15.066 14.52 ;
    END
  END q[43]
  PIN q[44]
    DIRECTION OUTPUT ;
    USE SIGNAL ;
    PORT
      LAYER M4 ;
        RECT  14.982 14.688 15.066 14.712 ;
    END
  END q[44]
  PIN q[45]
    DIRECTION OUTPUT ;
    USE SIGNAL ;
    PORT
      LAYER M4 ;
        RECT  14.982 14.928 15.066 14.952 ;
    END
  END q[45]
  PIN q[46]
    DIRECTION OUTPUT ;
    USE SIGNAL ;
    PORT
      LAYER M4 ;
        RECT  14.982 15.12 15.066 15.144 ;
    END
  END q[46]
  PIN q[47]
    DIRECTION OUTPUT ;
    USE SIGNAL ;
    PORT
      LAYER M4 ;
        RECT  14.982 15.36 15.066 15.384 ;
    END
  END q[47]
  PIN q[48]
    DIRECTION OUTPUT ;
    USE SIGNAL ;
    PORT
      LAYER M4 ;
        RECT  14.982 15.552 15.066 15.576 ;
    END
  END q[48]
  PIN q[49]
    DIRECTION OUTPUT ;
    USE SIGNAL ;
    PORT
      LAYER M4 ;
        RECT  14.982 15.744 15.066 15.768 ;
    END
  END q[49]
  PIN q[4]
    DIRECTION OUTPUT ;
    USE SIGNAL ;
    PORT
      LAYER M4 ;
        RECT  14.982 6.24 15.066 6.264 ;
    END
  END q[4]
  PIN q[50]
    DIRECTION OUTPUT ;
    USE SIGNAL ;
    PORT
      LAYER M4 ;
        RECT  14.982 15.984 15.066 16.008 ;
    END
  END q[50]
  PIN q[51]
    DIRECTION OUTPUT ;
    USE SIGNAL ;
    PORT
      LAYER M4 ;
        RECT  14.982 16.176 15.066 16.2 ;
    END
  END q[51]
  PIN q[52]
    DIRECTION OUTPUT ;
    USE SIGNAL ;
    PORT
      LAYER M4 ;
        RECT  14.982 16.416 15.066 16.44 ;
    END
  END q[52]
  PIN q[53]
    DIRECTION OUTPUT ;
    USE SIGNAL ;
    PORT
      LAYER M4 ;
        RECT  14.982 16.608 15.066 16.632 ;
    END
  END q[53]
  PIN q[54]
    DIRECTION OUTPUT ;
    USE SIGNAL ;
    PORT
      LAYER M4 ;
        RECT  14.982 16.8 15.066 16.824 ;
    END
  END q[54]
  PIN q[55]
    DIRECTION OUTPUT ;
    USE SIGNAL ;
    PORT
      LAYER M4 ;
        RECT  14.982 17.04 15.066 17.064 ;
    END
  END q[55]
  PIN q[56]
    DIRECTION OUTPUT ;
    USE SIGNAL ;
    PORT
      LAYER M4 ;
        RECT  14.982 17.232 15.066 17.256 ;
    END
  END q[56]
  PIN q[57]
    DIRECTION OUTPUT ;
    USE SIGNAL ;
    PORT
      LAYER M4 ;
        RECT  14.982 17.472 15.066 17.496 ;
    END
  END q[57]
  PIN q[58]
    DIRECTION OUTPUT ;
    USE SIGNAL ;
    PORT
      LAYER M4 ;
        RECT  14.982 17.664 15.066 17.688 ;
    END
  END q[58]
  PIN q[59]
    DIRECTION OUTPUT ;
    USE SIGNAL ;
    PORT
      LAYER M4 ;
        RECT  14.982 17.904 15.066 17.928 ;
    END
  END q[59]
  PIN q[5]
    DIRECTION OUTPUT ;
    USE SIGNAL ;
    PORT
      LAYER M4 ;
        RECT  14.982 6.432 15.066 6.456 ;
    END
  END q[5]
  PIN q[60]
    DIRECTION OUTPUT ;
    USE SIGNAL ;
    PORT
      LAYER M4 ;
        RECT  14.982 18.096 15.066 18.12 ;
    END
  END q[60]
  PIN q[61]
    DIRECTION OUTPUT ;
    USE SIGNAL ;
    PORT
      LAYER M4 ;
        RECT  14.982 18.288 15.066 18.312 ;
    END
  END q[61]
  PIN q[62]
    DIRECTION OUTPUT ;
    USE SIGNAL ;
    PORT
      LAYER M4 ;
        RECT  14.982 18.528 15.066 18.552 ;
    END
  END q[62]
  PIN q[63]
    DIRECTION OUTPUT ;
    USE SIGNAL ;
    PORT
      LAYER M4 ;
        RECT  14.982 18.72 15.066 18.744 ;
    END
  END q[63]
  PIN q[64]
    DIRECTION OUTPUT ;
    USE SIGNAL ;
    PORT
      LAYER M4 ;
        RECT  14.982 18.96 15.066 18.984 ;
    END
  END q[64]
  PIN q[65]
    DIRECTION OUTPUT ;
    USE SIGNAL ;
    PORT
      LAYER M4 ;
        RECT  14.982 19.152 15.066 19.176 ;
    END
  END q[65]
  PIN q[66]
    DIRECTION OUTPUT ;
    USE SIGNAL ;
    PORT
      LAYER M4 ;
        RECT  14.982 19.344 15.066 19.368 ;
    END
  END q[66]
  PIN q[67]
    DIRECTION OUTPUT ;
    USE SIGNAL ;
    PORT
      LAYER M4 ;
        RECT  14.982 19.584 15.066 19.608 ;
    END
  END q[67]
  PIN q[68]
    DIRECTION OUTPUT ;
    USE SIGNAL ;
    PORT
      LAYER M4 ;
        RECT  14.982 19.776 15.066 19.8 ;
    END
  END q[68]
  PIN q[69]
    DIRECTION OUTPUT ;
    USE SIGNAL ;
    PORT
      LAYER M4 ;
        RECT  14.982 20.016 15.066 20.04 ;
    END
  END q[69]
  PIN q[6]
    DIRECTION OUTPUT ;
    USE SIGNAL ;
    PORT
      LAYER M4 ;
        RECT  14.982 6.672 15.066 6.696 ;
    END
  END q[6]
  PIN q[70]
    DIRECTION OUTPUT ;
    USE SIGNAL ;
    PORT
      LAYER M4 ;
        RECT  14.982 20.208 15.066 20.232 ;
    END
  END q[70]
  PIN q[71]
    DIRECTION OUTPUT ;
    USE SIGNAL ;
    PORT
      LAYER M4 ;
        RECT  14.982 20.4 15.066 20.424 ;
    END
  END q[71]
  PIN q[72]
    DIRECTION OUTPUT ;
    USE SIGNAL ;
    PORT
      LAYER M4 ;
        RECT  14.982 20.64 15.066 20.664 ;
    END
  END q[72]
  PIN q[73]
    DIRECTION OUTPUT ;
    USE SIGNAL ;
    PORT
      LAYER M4 ;
        RECT  14.982 20.832 15.066 20.856 ;
    END
  END q[73]
  PIN q[74]
    DIRECTION OUTPUT ;
    USE SIGNAL ;
    PORT
      LAYER M4 ;
        RECT  14.982 21.072 15.066 21.096 ;
    END
  END q[74]
  PIN q[75]
    DIRECTION OUTPUT ;
    USE SIGNAL ;
    PORT
      LAYER M4 ;
        RECT  14.982 21.264 15.066 21.288 ;
    END
  END q[75]
  PIN q[76]
    DIRECTION OUTPUT ;
    USE SIGNAL ;
    PORT
      LAYER M4 ;
        RECT  14.982 21.504 15.066 21.528 ;
    END
  END q[76]
  PIN q[77]
    DIRECTION OUTPUT ;
    USE SIGNAL ;
    PORT
      LAYER M4 ;
        RECT  14.982 21.696 15.066 21.72 ;
    END
  END q[77]
  PIN q[78]
    DIRECTION OUTPUT ;
    USE SIGNAL ;
    PORT
      LAYER M4 ;
        RECT  14.982 21.888 15.066 21.912 ;
    END
  END q[78]
  PIN q[79]
    DIRECTION OUTPUT ;
    USE SIGNAL ;
    PORT
      LAYER M4 ;
        RECT  14.982 22.128 15.066 22.152 ;
    END
  END q[79]
  PIN q[7]
    DIRECTION OUTPUT ;
    USE SIGNAL ;
    PORT
      LAYER M4 ;
        RECT  14.982 6.864 15.066 6.888 ;
    END
  END q[7]
  PIN q[80]
    DIRECTION OUTPUT ;
    USE SIGNAL ;
    PORT
      LAYER M4 ;
        RECT  14.982 22.32 15.066 22.344 ;
    END
  END q[80]
  PIN q[81]
    DIRECTION OUTPUT ;
    USE SIGNAL ;
    PORT
      LAYER M4 ;
        RECT  14.982 22.56 15.066 22.584 ;
    END
  END q[81]
  PIN q[82]
    DIRECTION OUTPUT ;
    USE SIGNAL ;
    PORT
      LAYER M4 ;
        RECT  14.982 22.752 15.066 22.776 ;
    END
  END q[82]
  PIN q[83]
    DIRECTION OUTPUT ;
    USE SIGNAL ;
    PORT
      LAYER M4 ;
        RECT  14.982 22.944 15.066 22.968 ;
    END
  END q[83]
  PIN q[84]
    DIRECTION OUTPUT ;
    USE SIGNAL ;
    PORT
      LAYER M4 ;
        RECT  14.982 23.184 15.066 23.208 ;
    END
  END q[84]
  PIN q[85]
    DIRECTION OUTPUT ;
    USE SIGNAL ;
    PORT
      LAYER M4 ;
        RECT  14.982 23.376 15.066 23.4 ;
    END
  END q[85]
  PIN q[86]
    DIRECTION OUTPUT ;
    USE SIGNAL ;
    PORT
      LAYER M4 ;
        RECT  14.982 23.616 15.066 23.64 ;
    END
  END q[86]
  PIN q[87]
    DIRECTION OUTPUT ;
    USE SIGNAL ;
    PORT
      LAYER M4 ;
        RECT  14.982 23.808 15.066 23.832 ;
    END
  END q[87]
  PIN q[88]
    DIRECTION OUTPUT ;
    USE SIGNAL ;
    PORT
      LAYER M4 ;
        RECT  14.982 24 15.066 24.024 ;
    END
  END q[88]
  PIN q[89]
    DIRECTION OUTPUT ;
    USE SIGNAL ;
    PORT
      LAYER M4 ;
        RECT  14.982 24.24 15.066 24.264 ;
    END
  END q[89]
  PIN q[8]
    DIRECTION OUTPUT ;
    USE SIGNAL ;
    PORT
      LAYER M4 ;
        RECT  14.982 7.104 15.066 7.128 ;
    END
  END q[8]
  PIN q[90]
    DIRECTION OUTPUT ;
    USE SIGNAL ;
    PORT
      LAYER M4 ;
        RECT  14.982 24.432 15.066 24.456 ;
    END
  END q[90]
  PIN q[91]
    DIRECTION OUTPUT ;
    USE SIGNAL ;
    PORT
      LAYER M4 ;
        RECT  14.982 24.672 15.066 24.696 ;
    END
  END q[91]
  PIN q[92]
    DIRECTION OUTPUT ;
    USE SIGNAL ;
    PORT
      LAYER M4 ;
        RECT  14.982 24.864 15.066 24.888 ;
    END
  END q[92]
  PIN q[93]
    DIRECTION OUTPUT ;
    USE SIGNAL ;
    PORT
      LAYER M4 ;
        RECT  14.982 25.104 15.066 25.128 ;
    END
  END q[93]
  PIN q[94]
    DIRECTION OUTPUT ;
    USE SIGNAL ;
    PORT
      LAYER M4 ;
        RECT  14.982 25.296 15.066 25.32 ;
    END
  END q[94]
  PIN q[95]
    DIRECTION OUTPUT ;
    USE SIGNAL ;
    PORT
      LAYER M4 ;
        RECT  14.982 25.488 15.066 25.512 ;
    END
  END q[95]
  PIN q[96]
    DIRECTION OUTPUT ;
    USE SIGNAL ;
    PORT
      LAYER M4 ;
        RECT  14.982 25.728 15.066 25.752 ;
    END
  END q[96]
  PIN q[97]
    DIRECTION OUTPUT ;
    USE SIGNAL ;
    PORT
      LAYER M4 ;
        RECT  14.982 25.92 15.066 25.944 ;
    END
  END q[97]
  PIN q[98]
    DIRECTION OUTPUT ;
    USE SIGNAL ;
    PORT
      LAYER M4 ;
        RECT  14.982 26.16 15.066 26.184 ;
    END
  END q[98]
  PIN q[99]
    DIRECTION OUTPUT ;
    USE SIGNAL ;
    PORT
      LAYER M4 ;
        RECT  14.982 26.352 15.066 26.376 ;
    END
  END q[99]
  PIN q[9]
    DIRECTION OUTPUT ;
    USE SIGNAL ;
    PORT
      LAYER M4 ;
        RECT  14.982 7.296 15.066 7.32 ;
    END
  END q[9]
  PIN rst_n
    DIRECTION INPUT ;
    USE SIGNAL ;
    PORT
      LAYER M5 ;
        RECT  9.696 0.054 9.72 0.138 ;
    END
    PORT
      LAYER M5 ;
        RECT  9.696 0.08 9.72 0.611 ;
    END
  END rst_n
  PIN VDD
    DIRECTION INOUT ;
    USE POWER ;
    PORT
      LAYER M5 ;
        RECT  10.692 2.151 10.812 62.649 ;
        RECT  7.992 2.151 8.112 62.649 ;
        RECT  5.292 2.151 5.412 62.649 ;
        RECT  2.592 2.151 2.712 62.649 ;
    END
  END VDD
  PIN VSS
    DIRECTION INOUT ;
    USE GROUND ;
    PORT
      LAYER M5 ;
        RECT  10.5 2.137 10.62 62.663 ;
        RECT  7.8 2.137 7.92 62.663 ;
        RECT  5.1 2.137 5.22 62.663 ;
        RECT  2.4 2.137 2.52 62.663 ;
    END
  END VSS
  # OT_OBS_CLOSED layer=M5 d_um=1.536 added=20
  OBS
    LAYER RVTN ;
     RECT  2.16 2.16 12.96 2.295 ;
     RECT  2.16 2.565 12.96 2.835 ;
     RECT  2.16 3.105 12.96 3.375 ;
     RECT  2.16 3.645 12.96 3.915 ;
     RECT  2.16 4.185 12.96 4.455 ;
     RECT  2.16 4.725 12.96 4.995 ;
     RECT  2.16 5.265 12.96 5.535 ;
     RECT  2.16 5.805 12.96 6.075 ;
     RECT  2.16 6.345 12.96 6.615 ;
     RECT  2.16 6.885 12.96 7.155 ;
     RECT  2.16 7.425 12.96 7.695 ;
     RECT  2.16 7.965 12.96 8.235 ;
     RECT  2.16 8.505 12.96 8.775 ;
     RECT  2.16 9.045 12.96 9.315 ;
     RECT  2.16 9.585 12.96 9.855 ;
     RECT  2.16 10.125 12.96 10.395 ;
     RECT  2.16 10.665 12.96 10.935 ;
     RECT  2.16 11.205 12.96 11.475 ;
     RECT  2.16 11.745 12.96 12.015 ;
     RECT  2.16 12.285 12.96 12.555 ;
     RECT  2.16 12.825 12.96 13.095 ;
     RECT  2.16 13.365 12.96 13.635 ;
     RECT  2.16 13.905 12.96 14.175 ;
     RECT  2.16 14.445 12.96 14.715 ;
     RECT  2.16 14.985 12.96 15.255 ;
     RECT  2.16 15.525 12.96 15.795 ;
     RECT  2.16 16.065 12.96 16.335 ;
     RECT  2.16 16.605 12.96 16.875 ;
     RECT  2.16 17.145 12.96 17.415 ;
     RECT  2.16 17.685 12.96 17.955 ;
     RECT  2.16 18.225 12.96 18.495 ;
     RECT  2.16 18.765 12.96 19.035 ;
     RECT  2.16 19.305 12.96 19.575 ;
     RECT  2.16 19.845 12.96 20.115 ;
     RECT  2.16 20.385 12.96 20.655 ;
     RECT  2.16 20.925 12.96 21.195 ;
     RECT  2.16 21.465 12.96 21.735 ;
     RECT  2.16 22.005 12.96 22.275 ;
     RECT  2.16 22.545 12.96 22.815 ;
     RECT  2.16 23.085 12.96 23.355 ;
     RECT  2.16 23.625 12.96 23.895 ;
     RECT  2.16 24.165 12.96 24.435 ;
     RECT  2.16 24.705 12.96 24.975 ;
     RECT  2.16 25.245 12.96 25.515 ;
     RECT  2.16 25.785 12.96 26.055 ;
     RECT  2.16 26.325 12.96 26.595 ;
     RECT  2.16 26.865 12.96 27.135 ;
     RECT  2.16 27.405 12.96 27.675 ;
     RECT  2.16 27.945 12.96 28.215 ;
     RECT  2.16 28.485 12.96 28.755 ;
     RECT  2.16 29.025 12.96 29.295 ;
     RECT  2.16 29.565 12.96 29.835 ;
     RECT  2.16 30.105 12.96 30.375 ;
     RECT  2.16 30.645 12.96 30.915 ;
     RECT  2.16 31.185 12.96 31.455 ;
     RECT  2.16 31.725 12.96 31.995 ;
     RECT  2.16 32.265 12.96 32.535 ;
     RECT  2.16 32.805 12.96 33.075 ;
     RECT  2.16 33.345 12.96 33.615 ;
     RECT  2.16 33.885 12.96 34.155 ;
     RECT  2.16 34.425 12.96 34.695 ;
     RECT  2.16 34.965 12.96 35.235 ;
     RECT  2.16 35.505 12.96 35.775 ;
     RECT  2.16 36.045 12.96 36.315 ;
     RECT  2.16 36.585 12.96 36.855 ;
     RECT  2.16 37.125 12.96 37.395 ;
     RECT  2.16 37.665 12.96 37.935 ;
     RECT  2.16 38.205 12.96 38.475 ;
     RECT  2.16 38.745 12.96 39.015 ;
     RECT  2.16 39.285 12.96 39.555 ;
     RECT  2.16 39.825 12.96 40.095 ;
     RECT  2.16 40.365 12.96 40.635 ;
     RECT  2.16 40.905 12.96 41.175 ;
     RECT  2.16 41.445 12.96 41.715 ;
     RECT  2.16 41.985 12.96 42.255 ;
     RECT  2.16 42.525 12.96 42.795 ;
     RECT  2.16 43.065 12.96 43.335 ;
     RECT  2.16 43.605 12.96 43.875 ;
     RECT  2.16 44.145 12.96 44.415 ;
     RECT  2.16 44.685 12.96 44.955 ;
     RECT  2.16 45.225 12.96 45.495 ;
     RECT  2.16 45.765 12.96 46.035 ;
     RECT  2.16 46.305 12.96 46.575 ;
     RECT  2.16 46.845 12.96 47.115 ;
     RECT  2.16 47.385 12.96 47.655 ;
     RECT  2.16 47.925 12.96 48.195 ;
     RECT  2.16 48.465 12.96 48.735 ;
     RECT  2.16 49.005 12.96 49.275 ;
     RECT  2.16 49.545 12.96 49.815 ;
     RECT  2.16 50.085 12.96 50.355 ;
     RECT  2.16 50.625 12.96 50.895 ;
     RECT  2.16 51.165 12.96 51.435 ;
     RECT  2.16 51.705 12.96 51.975 ;
     RECT  2.16 52.245 12.96 52.515 ;
     RECT  2.16 52.785 12.96 53.055 ;
     RECT  2.16 53.325 12.96 53.595 ;
     RECT  2.16 53.865 12.96 54.135 ;
     RECT  2.16 54.405 12.96 54.675 ;
     RECT  2.16 54.945 12.96 55.215 ;
     RECT  2.16 55.485 12.96 55.755 ;
     RECT  2.16 56.025 12.96 56.295 ;
     RECT  2.16 56.565 12.96 56.835 ;
     RECT  2.16 57.105 12.96 57.375 ;
     RECT  2.16 57.645 12.96 57.915 ;
     RECT  2.16 58.185 12.96 58.455 ;
     RECT  2.16 58.725 12.96 58.995 ;
     RECT  2.16 59.265 12.96 59.535 ;
     RECT  2.16 59.805 12.96 60.075 ;
     RECT  2.16 60.345 12.96 60.615 ;
     RECT  2.16 60.885 12.96 61.155 ;
     RECT  2.16 61.425 12.96 61.695 ;
     RECT  2.16 61.965 12.96 62.235 ;
     RECT  2.16 62.505 12.96 62.64 ;
    LAYER RVTP ;
     RECT  2.16 2.295 12.96 2.565 ;
     RECT  2.16 2.835 12.96 3.105 ;
     RECT  2.16 3.375 12.96 3.645 ;
     RECT  2.16 3.915 12.96 4.185 ;
     RECT  2.16 4.455 12.96 4.725 ;
     RECT  2.16 4.995 12.96 5.265 ;
     RECT  2.16 5.535 12.96 5.805 ;
     RECT  2.16 6.075 12.96 6.345 ;
     RECT  2.16 6.615 12.96 6.885 ;
     RECT  2.16 7.155 12.96 7.425 ;
     RECT  2.16 7.695 12.96 7.965 ;
     RECT  2.16 8.235 12.96 8.505 ;
     RECT  2.16 8.775 12.96 9.045 ;
     RECT  2.16 9.315 12.96 9.585 ;
     RECT  2.16 9.855 12.96 10.125 ;
     RECT  2.16 10.395 12.96 10.665 ;
     RECT  2.16 10.935 12.96 11.205 ;
     RECT  2.16 11.475 12.96 11.745 ;
     RECT  2.16 12.015 12.96 12.285 ;
     RECT  2.16 12.555 12.96 12.825 ;
     RECT  2.16 13.095 12.96 13.365 ;
     RECT  2.16 13.635 12.96 13.905 ;
     RECT  2.16 14.175 12.96 14.445 ;
     RECT  2.16 14.715 12.96 14.985 ;
     RECT  2.16 15.255 12.96 15.525 ;
     RECT  2.16 15.795 12.96 16.065 ;
     RECT  2.16 16.335 12.96 16.605 ;
     RECT  2.16 16.875 12.96 17.145 ;
     RECT  2.16 17.415 12.96 17.685 ;
     RECT  2.16 17.955 12.96 18.225 ;
     RECT  2.16 18.495 12.96 18.765 ;
     RECT  2.16 19.035 12.96 19.305 ;
     RECT  2.16 19.575 12.96 19.845 ;
     RECT  2.16 20.115 12.96 20.385 ;
     RECT  2.16 20.655 12.96 20.925 ;
     RECT  2.16 21.195 12.96 21.465 ;
     RECT  2.16 21.735 12.96 22.005 ;
     RECT  2.16 22.275 12.96 22.545 ;
     RECT  2.16 22.815 12.96 23.085 ;
     RECT  2.16 23.355 12.96 23.625 ;
     RECT  2.16 23.895 12.96 24.165 ;
     RECT  2.16 24.435 12.96 24.705 ;
     RECT  2.16 24.975 12.96 25.245 ;
     RECT  2.16 25.515 12.96 25.785 ;
     RECT  2.16 26.055 12.96 26.325 ;
     RECT  2.16 26.595 12.96 26.865 ;
     RECT  2.16 27.135 12.96 27.405 ;
     RECT  2.16 27.675 12.96 27.945 ;
     RECT  2.16 28.215 12.96 28.485 ;
     RECT  2.16 28.755 12.96 29.025 ;
     RECT  2.16 29.295 12.96 29.565 ;
     RECT  2.16 29.835 12.96 30.105 ;
     RECT  2.16 30.375 12.96 30.645 ;
     RECT  2.16 30.915 12.96 31.185 ;
     RECT  2.16 31.455 12.96 31.725 ;
     RECT  2.16 31.995 12.96 32.265 ;
     RECT  2.16 32.535 12.96 32.805 ;
     RECT  2.16 33.075 12.96 33.345 ;
     RECT  2.16 33.615 12.96 33.885 ;
     RECT  2.16 34.155 12.96 34.425 ;
     RECT  2.16 34.695 12.96 34.965 ;
     RECT  2.16 35.235 12.96 35.505 ;
     RECT  2.16 35.775 12.96 36.045 ;
     RECT  2.16 36.315 12.96 36.585 ;
     RECT  2.16 36.855 12.96 37.125 ;
     RECT  2.16 37.395 12.96 37.665 ;
     RECT  2.16 37.935 12.96 38.205 ;
     RECT  2.16 38.475 12.96 38.745 ;
     RECT  2.16 39.015 12.96 39.285 ;
     RECT  2.16 39.555 12.96 39.825 ;
     RECT  2.16 40.095 12.96 40.365 ;
     RECT  2.16 40.635 12.96 40.905 ;
     RECT  2.16 41.175 12.96 41.445 ;
     RECT  2.16 41.715 12.96 41.985 ;
     RECT  2.16 42.255 12.96 42.525 ;
     RECT  2.16 42.795 12.96 43.065 ;
     RECT  2.16 43.335 12.96 43.605 ;
     RECT  2.16 43.875 12.96 44.145 ;
     RECT  2.16 44.415 12.96 44.685 ;
     RECT  2.16 44.955 12.96 45.225 ;
     RECT  2.16 45.495 12.96 45.765 ;
     RECT  2.16 46.035 12.96 46.305 ;
     RECT  2.16 46.575 12.96 46.845 ;
     RECT  2.16 47.115 12.96 47.385 ;
     RECT  2.16 47.655 12.96 47.925 ;
     RECT  2.16 48.195 12.96 48.465 ;
     RECT  2.16 48.735 12.96 49.005 ;
     RECT  2.16 49.275 12.96 49.545 ;
     RECT  2.16 49.815 12.96 50.085 ;
     RECT  2.16 50.355 12.96 50.625 ;
     RECT  2.16 50.895 12.96 51.165 ;
     RECT  2.16 51.435 12.96 51.705 ;
     RECT  2.16 51.975 12.96 52.245 ;
     RECT  2.16 52.515 12.96 52.785 ;
     RECT  2.16 53.055 12.96 53.325 ;
     RECT  2.16 53.595 12.96 53.865 ;
     RECT  2.16 54.135 12.96 54.405 ;
     RECT  2.16 54.675 12.96 54.945 ;
     RECT  2.16 55.215 12.96 55.485 ;
     RECT  2.16 55.755 12.96 56.025 ;
     RECT  2.16 56.295 12.96 56.565 ;
     RECT  2.16 56.835 12.96 57.105 ;
     RECT  2.16 57.375 12.96 57.645 ;
     RECT  2.16 57.915 12.96 58.185 ;
     RECT  2.16 58.455 12.96 58.725 ;
     RECT  2.16 58.995 12.96 59.265 ;
     RECT  2.16 59.535 12.96 59.805 ;
     RECT  2.16 60.075 12.96 60.345 ;
     RECT  2.16 60.615 12.96 60.885 ;
     RECT  2.16 61.155 12.96 61.425 ;
     RECT  2.16 61.695 12.96 61.965 ;
     RECT  2.16 62.235 12.96 62.505 ;
    LAYER M1 ;
     RECT  2.16 2.151 12.96 62.649 ;
    LAYER M2 ;
     RECT  0.139 4.77 0.175 4.788 ;
     RECT  0.175 4.77 2.16 5.256 ;
     RECT  0.139 6.39 2.16 6.408 ;
     RECT  0.175 10.17 2.16 10.188 ;
     RECT  0.139 18.702 2.16 18.72 ;
     RECT  0.139 27.342 2.16 27.36 ;
     RECT  0.139 38.142 2.16 38.16 ;
     RECT  0.139 55.26 2.16 55.278 ;
     RECT  2.16 2.151 12.96 62.649 ;
     RECT  12.96 4.266 13.667 59.184 ;
     RECT  13.667 18.432 13.883 24.624 ;
     RECT  13.667 25.416 13.955 58.374 ;
     RECT  13.667 4.266 14.207 17.676 ;
     RECT  13.955 25.416 14.207 57.294 ;
     RECT  14.207 4.266 14.243 13.014 ;
     RECT  14.207 13.806 14.243 17.676 ;
     RECT  13.883 18.432 14.243 22.23 ;
     RECT  13.883 23.166 14.243 24.624 ;
     RECT  14.207 25.416 14.243 36.144 ;
     RECT  14.207 37.026 14.243 49.734 ;
     RECT  14.207 50.526 14.243 57.294 ;
     RECT  13.955 58.356 14.243 58.374 ;
     RECT  13.667 59.166 14.243 59.184 ;
     RECT  14.243 4.266 14.279 6.84 ;
     RECT  14.243 32.436 14.279 32.454 ;
     RECT  14.243 33.318 14.279 33.336 ;
     RECT  14.243 43.686 14.279 43.794 ;
     RECT  14.243 49.248 14.279 49.266 ;
     RECT  14.243 51.066 14.279 54.504 ;
     RECT  14.243 55.962 14.279 55.98 ;
     RECT  14.279 4.266 14.891 5.364 ;
     RECT  12.96 60.246 14.891 60.804 ;
     RECT  14.891 4.266 14.927 4.824 ;
     RECT  14.243 16.956 14.927 17.334 ;
     RECT  14.279 51.066 14.927 51.624 ;
     RECT  14.279 52.866 14.927 54.504 ;
     RECT  14.891 60.246 14.927 60.534 ;
     RECT  14.927 4.266 14.963 4.284 ;
     RECT  14.279 6.156 14.963 6.84 ;
     RECT  14.243 10.296 14.963 10.314 ;
     RECT  14.243 12.996 14.963 13.014 ;
     RECT  14.243 15.228 14.963 15.246 ;
     RECT  14.927 17.316 14.963 17.334 ;
     RECT  14.243 18.774 14.963 18.792 ;
     RECT  14.243 21.096 14.963 22.23 ;
     RECT  14.243 23.328 14.963 23.814 ;
     RECT  14.243 26.226 14.963 27.36 ;
     RECT  14.243 30.726 14.963 30.744 ;
     RECT  14.243 36.126 14.963 36.144 ;
     RECT  14.243 37.404 14.963 38.124 ;
     RECT  14.243 40.338 14.963 40.356 ;
     RECT  14.279 43.686 14.963 43.704 ;
     RECT  14.243 45 14.963 45.018 ;
     RECT  14.243 46.656 14.963 46.908 ;
     RECT  14.243 48.438 14.963 48.456 ;
     RECT  14.927 51.066 14.963 51.084 ;
     RECT  14.927 52.992 14.963 54.504 ;
     RECT  14.927 60.246 14.963 60.264 ;
    LAYER M3 ;
     RECT  9.684 0.571 9.702 2.255 ;
     RECT  9.468 2.263 9.486 2.371 ;
     RECT  9.252 2.371 9.486 2.399 ;
     RECT  2.415 2.143 2.505 2.413 ;
     RECT  5.115 2.143 5.205 2.413 ;
     RECT  7.815 2.143 7.905 2.413 ;
     RECT  10.515 2.143 10.605 2.413 ;
     RECT  9.252 2.399 9.27 2.525 ;
     RECT  7.815 2.413 8.097 2.641 ;
     RECT  7.815 2.641 8.91 2.795 ;
     RECT  7.815 2.795 8.622 2.803 ;
     RECT  7.2 2.803 8.622 2.861 ;
     RECT  7.38 2.861 8.622 2.939 ;
     RECT  7.38 2.939 8.406 3.029 ;
     RECT  7.815 3.029 8.406 3.721 ;
     RECT  9.144 3.685 9.162 3.721 ;
     RECT  10.515 2.413 10.797 3.811 ;
     RECT  7.815 3.721 9.162 3.983 ;
     RECT  10.515 3.811 11.394 4.189 ;
     RECT  5.115 2.413 5.397 4.261 ;
     RECT  7.815 3.983 8.694 4.289 ;
     RECT  14.94 4.261 14.958 4.351 ;
     RECT  7.815 4.289 8.586 4.411 ;
     RECT  10.515 4.189 11.43 4.531 ;
     RECT  12.348 4.225 12.654 4.531 ;
     RECT  9.54 3.991 9.558 4.621 ;
     RECT  9.54 4.621 9.63 4.649 ;
     RECT  9.612 4.649 9.63 4.721 ;
     RECT  2.415 2.413 2.697 4.801 ;
     RECT  10.515 4.531 12.654 4.919 ;
     RECT  2.415 4.801 2.898 5.035 ;
     RECT  2.415 5.035 3.294 5.071 ;
     RECT  7.308 4.411 8.586 5.071 ;
     RECT  0.144 4.765 0.162 5.233 ;
     RECT  10.515 4.919 12.618 5.261 ;
     RECT  2.415 5.071 3.474 5.305 ;
     RECT  2.304 5.305 3.474 5.341 ;
     RECT  2.304 5.341 3.69 5.431 ;
     RECT  0.144 5.233 0.198 5.453 ;
     RECT  7.308 5.071 8.658 5.611 ;
     RECT  10.515 5.261 12.474 5.639 ;
     RECT  5.115 4.261 5.85 5.737 ;
     RECT  6.768 5.611 8.658 5.737 ;
     RECT  2.304 5.431 4.194 5.809 ;
     RECT  5.115 5.737 8.658 5.809 ;
     RECT  0.18 5.453 0.198 5.837 ;
     RECT  14.256 4.351 14.958 5.881 ;
     RECT  10.515 5.639 12.186 5.999 ;
     RECT  14.22 5.881 14.958 6.029 ;
     RECT  2.304 5.809 8.658 6.115 ;
     RECT  10.515 5.999 11.214 6.241 ;
     RECT  2.304 6.115 8.946 6.269 ;
     RECT  14.256 6.029 14.958 6.269 ;
     RECT  10.332 6.241 11.214 6.691 ;
     RECT  11.988 5.999 12.186 6.691 ;
     RECT  11.988 6.691 12.474 6.781 ;
     RECT  9.792 6.691 11.214 6.809 ;
     RECT  10.332 6.809 11.214 6.817 ;
     RECT  11.988 6.781 12.618 6.817 ;
     RECT  14.868 6.269 14.958 6.893 ;
     RECT  2.304 6.269 8.91 7.115 ;
     RECT  14.22 7.051 14.238 7.231 ;
     RECT  10.332 6.817 12.618 7.321 ;
     RECT  10.332 7.321 12.762 7.349 ;
     RECT  0.144 6.385 0.162 7.421 ;
     RECT  10.404 7.349 12.762 7.421 ;
     RECT  9.36 7.735 9.378 7.889 ;
     RECT  10.404 7.421 12.618 7.889 ;
     RECT  2.304 7.115 8.622 7.897 ;
     RECT  2.304 7.897 8.838 7.925 ;
     RECT  13.68 7.231 14.238 8.131 ;
     RECT  0.144 8.347 0.162 8.477 ;
     RECT  9.648 8.581 9.666 8.699 ;
     RECT  2.34 7.925 8.838 8.779 ;
     RECT  2.304 8.779 8.838 8.815 ;
     RECT  13.644 8.131 14.238 8.879 ;
     RECT  2.304 8.815 8.874 8.969 ;
     RECT  13.68 8.879 14.238 9.245 ;
     RECT  10.515 7.889 12.618 9.391 ;
     RECT  10.008 9.391 12.618 9.509 ;
     RECT  14.22 9.245 14.238 9.595 ;
     RECT  10.404 9.509 12.618 9.689 ;
     RECT  2.304 8.969 8.838 9.779 ;
     RECT  4.068 9.779 8.838 10.057 ;
     RECT  14.22 9.595 14.958 10.061 ;
     RECT  0.144 9.403 0.162 10.156 ;
     RECT  0.144 10.156 0.198 10.157 ;
     RECT  10.515 9.689 12.618 10.165 ;
     RECT  0.18 10.157 0.198 10.301 ;
     RECT  14.94 10.061 14.958 10.319 ;
     RECT  4.068 10.057 8.91 10.355 ;
     RECT  10.515 10.165 12.654 10.399 ;
     RECT  13.68 10.201 13.698 10.399 ;
     RECT  10.515 10.399 13.698 10.471 ;
     RECT  10.404 10.471 13.698 10.493 ;
     RECT  2.304 9.779 3.33 10.741 ;
     RECT  4.068 10.355 8.586 10.741 ;
     RECT  13.644 10.493 13.698 10.831 ;
     RECT  9.648 10.741 9.666 10.859 ;
     RECT  10.404 10.493 12.654 11.101 ;
     RECT  9.936 11.101 12.654 11.129 ;
     RECT  2.304 10.741 8.586 11.137 ;
     RECT  9.936 11.129 12.546 11.201 ;
     RECT  2.304 11.137 8.838 11.281 ;
     RECT  2.304 11.281 9.018 11.399 ;
     RECT  13.644 10.831 14.238 11.515 ;
     RECT  13.608 11.515 14.238 11.741 ;
     RECT  9.936 11.201 10.962 11.821 ;
     RECT  9.792 11.821 10.962 11.939 ;
     RECT  11.952 11.201 12.546 11.947 ;
     RECT  10.515 11.939 10.962 12.055 ;
     RECT  11.952 11.947 12.618 12.055 ;
     RECT  2.304 11.399 8.874 12.209 ;
     RECT  9.648 12.091 9.666 12.209 ;
     RECT  2.304 12.209 8.586 12.361 ;
     RECT  2.268 12.361 8.586 12.413 ;
     RECT  10.515 12.055 12.618 12.479 ;
     RECT  12.024 12.479 12.618 12.991 ;
     RECT  13.644 11.741 14.238 12.991 ;
     RECT  12.024 12.991 12.762 13.091 ;
     RECT  13.644 12.991 14.958 13.091 ;
     RECT  2.304 12.413 8.586 13.135 ;
     RECT  2.304 13.135 8.874 13.289 ;
     RECT  10.515 12.479 11.286 13.369 ;
     RECT  12.024 13.091 12.654 13.369 ;
     RECT  9.756 13.441 9.774 13.531 ;
     RECT  9.684 13.531 9.774 13.981 ;
     RECT  10.515 13.369 12.654 13.981 ;
     RECT  9.684 13.981 12.654 14.099 ;
     RECT  9.684 14.099 12.51 14.207 ;
     RECT  14.184 13.091 14.958 14.251 ;
     RECT  9.684 14.207 11.178 14.369 ;
     RECT  2.304 13.289 8.838 14.405 ;
     RECT  6.552 14.405 8.838 14.521 ;
     RECT  6.552 14.521 9.378 14.639 ;
     RECT  11.988 14.207 12.51 15.025 ;
     RECT  10.512 14.369 11.178 15.061 ;
     RECT  11.988 15.025 12.582 15.061 ;
     RECT  13.644 14.251 14.958 15.179 ;
     RECT  14.22 15.179 14.958 15.251 ;
     RECT  2.304 14.405 5.778 15.295 ;
     RECT  6.552 14.639 8.874 15.295 ;
     RECT  10.512 15.061 12.582 15.331 ;
     RECT  0.144 15.259 0.162 15.389 ;
     RECT  2.304 15.295 8.874 15.529 ;
     RECT  10.26 15.331 12.582 15.529 ;
     RECT  10.26 15.529 12.834 15.719 ;
     RECT  2.304 15.529 9.342 15.827 ;
     RECT  10.44 15.719 12.834 15.979 ;
     RECT  10.44 15.979 13.086 16.169 ;
     RECT  14.22 15.251 14.238 16.259 ;
     RECT  10.44 16.169 12.834 16.529 ;
     RECT  2.304 15.827 8.946 16.771 ;
     RECT  10.44 16.529 12.762 16.799 ;
     RECT  13.644 16.411 13.698 16.829 ;
     RECT  2.304 16.771 9.09 16.871 ;
     RECT  0.144 16.891 0.162 17.069 ;
     RECT  14.904 16.411 14.958 17.339 ;
     RECT  14.904 17.339 14.922 17.501 ;
     RECT  13.644 16.829 13.662 17.653 ;
     RECT  10.44 16.799 12.618 17.689 ;
     RECT  13.644 17.653 14.238 17.693 ;
     RECT  10.404 17.689 12.618 17.879 ;
     RECT  10.404 17.879 12.582 17.923 ;
     RECT  2.304 16.871 8.838 17.995 ;
     RECT  2.304 17.995 8.874 18.031 ;
     RECT  2.304 18.031 9.306 18.149 ;
     RECT  10.26 17.923 12.582 18.149 ;
     RECT  10.404 18.149 12.582 18.185 ;
     RECT  13.644 17.693 13.662 18.427 ;
     RECT  13.644 18.427 14.238 18.499 ;
     RECT  13.608 18.499 14.238 18.557 ;
     RECT  13.644 18.557 14.238 18.599 ;
     RECT  10.515 18.185 12.582 18.769 ;
     RECT  14.22 18.599 14.238 18.769 ;
     RECT  9.576 18.571 9.594 18.959 ;
     RECT  2.304 18.149 8.838 18.995 ;
     RECT  10.515 18.769 12.654 19.111 ;
     RECT  14.22 18.769 14.958 19.181 ;
     RECT  9.792 19.111 12.654 19.229 ;
     RECT  0.144 18.697 0.162 19.277 ;
     RECT  14.22 19.181 14.238 19.579 ;
     RECT  2.415 18.995 8.586 19.768 ;
     RECT  2.304 19.768 8.586 19.777 ;
     RECT  13.86 19.579 14.238 20.011 ;
     RECT  10.26 19.229 12.654 20.039 ;
     RECT  2.304 19.777 8.838 20.111 ;
     RECT  13.536 20.011 14.238 20.147 ;
     RECT  10.296 20.039 12.654 20.309 ;
     RECT  5.115 20.111 8.838 20.461 ;
     RECT  5.115 20.461 9.486 20.579 ;
     RECT  2.304 20.111 4.194 20.669 ;
     RECT  13.644 20.147 14.238 20.827 ;
     RECT  5.115 20.579 9.306 20.849 ;
     RECT  10.296 20.309 12.582 20.849 ;
     RECT  10.296 20.849 12.474 20.921 ;
     RECT  0.144 20.203 0.162 20.971 ;
     RECT  13.644 20.827 14.274 21.067 ;
     RECT  2.34 20.669 4.194 21.091 ;
     RECT  5.115 20.849 9.126 21.091 ;
     RECT  0.144 20.971 0.234 21.101 ;
     RECT  2.34 21.091 9.126 21.119 ;
     RECT  2.34 21.119 8.91 21.499 ;
     RECT  2.304 21.499 8.91 21.677 ;
     RECT  13.644 21.067 14.958 21.929 ;
     RECT  0.144 21.101 0.162 22.013 ;
     RECT  10.515 20.921 12.474 22.081 ;
     RECT  13.644 21.929 13.878 22.157 ;
     RECT  10.515 22.081 12.546 22.207 ;
     RECT  2.304 21.677 8.874 22.253 ;
     RECT  14.94 21.929 14.958 22.349 ;
     RECT  10.515 22.207 12.618 22.747 ;
     RECT  10.515 22.747 13.122 22.811 ;
     RECT  13.86 22.157 13.878 22.939 ;
     RECT  2.304 22.253 3.222 23.035 ;
     RECT  4.032 22.253 8.874 23.035 ;
     RECT  0.144 22.939 0.162 23.069 ;
     RECT  13.644 22.939 13.878 23.081 ;
     RECT  2.304 23.035 8.874 23.161 ;
     RECT  2.304 23.161 9.306 23.279 ;
     RECT  14.22 23.161 14.238 23.323 ;
     RECT  10.515 22.811 12.618 23.701 ;
     RECT  14.22 23.323 14.958 23.803 ;
     RECT  10.188 23.701 12.618 23.819 ;
     RECT  13.644 23.803 14.958 23.891 ;
     RECT  14.22 23.891 14.958 24.029 ;
     RECT  2.304 23.279 8.874 24.089 ;
     RECT  10.224 23.819 12.618 24.629 ;
     RECT  10.515 24.629 12.618 24.667 ;
     RECT  10.515 24.667 13.086 24.781 ;
     RECT  10.515 24.781 13.122 24.935 ;
     RECT  12.024 24.935 13.122 24.971 ;
     RECT  9.648 24.979 9.666 25.079 ;
     RECT  14.22 24.029 14.238 25.099 ;
     RECT  12.024 24.971 12.654 25.475 ;
     RECT  2.304 24.089 8.838 25.555 ;
     RECT  10.515 24.935 11.214 25.591 ;
     RECT  10.008 25.591 11.214 25.681 ;
     RECT  12.024 25.475 12.222 25.681 ;
     RECT  2.304 25.555 8.874 25.709 ;
     RECT  10.008 25.681 12.222 25.709 ;
     RECT  2.304 25.709 8.586 25.915 ;
     RECT  13.644 25.099 14.238 25.979 ;
     RECT  2.268 25.915 8.586 26.015 ;
     RECT  14.22 25.979 14.238 26.155 ;
     RECT  0.144 26.059 0.162 26.189 ;
     RECT  10.515 25.709 12.222 26.365 ;
     RECT  2.304 26.015 8.586 26.393 ;
     RECT  9.54 26.131 9.558 26.429 ;
     RECT  10.515 26.365 12.33 26.491 ;
     RECT  13.068 26.293 13.086 26.491 ;
     RECT  10.515 26.491 13.086 26.573 ;
     RECT  2.34 26.393 8.586 26.635 ;
     RECT  2.34 26.635 8.838 26.825 ;
     RECT  10.515 26.573 12.618 26.825 ;
     RECT  14.22 26.155 14.958 26.971 ;
     RECT  2.34 26.825 4.194 27.211 ;
     RECT  10.515 26.825 12.33 27.211 ;
     RECT  9.972 27.211 12.33 27.329 ;
     RECT  5.115 26.825 8.838 27.337 ;
     RECT  0.144 26.971 0.162 27.437 ;
     RECT  13.644 26.971 14.958 27.437 ;
     RECT  10.515 27.329 12.33 27.473 ;
     RECT  13.644 27.437 14.238 27.595 ;
     RECT  13.536 27.595 14.238 27.743 ;
     RECT  2.304 27.211 4.194 27.841 ;
     RECT  5.115 27.337 8.91 27.841 ;
     RECT  2.304 27.841 8.91 28.021 ;
     RECT  2.304 28.021 9.306 28.139 ;
     RECT  10.515 27.473 11.862 28.291 ;
     RECT  12.6 27.679 12.618 28.291 ;
     RECT  13.644 27.743 14.238 28.493 ;
     RECT  10.515 28.291 12.618 28.723 ;
     RECT  10.26 28.723 12.618 28.751 ;
     RECT  2.304 28.139 8.946 29.029 ;
     RECT  2.304 29.029 9.45 29.255 ;
     RECT  14.22 28.493 14.238 29.263 ;
     RECT  10.26 28.751 12.402 29.605 ;
     RECT  9.684 29.605 12.402 29.759 ;
     RECT  2.304 29.255 8.766 29.795 ;
     RECT  9.972 29.759 12.402 29.875 ;
     RECT  13.644 29.263 14.238 30.413 ;
     RECT  9.972 29.875 12.582 30.451 ;
     RECT  2.34 29.795 8.766 30.568 ;
     RECT  2.304 30.568 8.766 30.577 ;
     RECT  9.972 30.451 13.122 30.605 ;
     RECT  9.972 30.605 12.582 30.721 ;
     RECT  14.22 30.413 14.238 30.721 ;
     RECT  9.576 30.721 12.582 30.749 ;
     RECT  14.22 30.721 14.958 30.845 ;
     RECT  9.576 30.749 12.402 30.875 ;
     RECT  2.304 30.577 8.838 31.495 ;
     RECT  9.864 30.875 12.402 31.495 ;
     RECT  2.304 31.495 8.874 31.649 ;
     RECT  9.864 31.495 12.654 31.721 ;
     RECT  14.22 30.845 14.238 31.867 ;
     RECT  0.216 31.675 0.234 31.901 ;
     RECT  0.144 32.059 0.162 32.237 ;
     RECT  13.644 31.867 14.238 32.26 ;
     RECT  2.304 31.649 8.586 32.261 ;
     RECT  13.608 32.26 14.238 32.333 ;
     RECT  13.644 32.333 14.238 32.431 ;
     RECT  7.272 32.261 8.586 32.575 ;
     RECT  10.224 31.721 12.654 32.729 ;
     RECT  2.304 32.261 6.426 32.881 ;
     RECT  2.268 32.881 6.426 32.957 ;
     RECT  10.224 32.729 12.582 33.035 ;
     RECT  10.224 33.035 12.294 33.313 ;
     RECT  2.304 32.957 6.426 33.349 ;
     RECT  7.272 32.575 8.874 33.349 ;
     RECT  2.304 33.349 8.874 33.421 ;
     RECT  9.792 33.313 12.294 33.421 ;
     RECT  2.304 33.421 12.294 33.539 ;
     RECT  13.644 32.431 14.274 33.581 ;
     RECT  9.792 33.539 12.294 33.925 ;
     RECT  2.304 33.539 8.874 34.349 ;
     RECT  9.792 33.925 12.618 34.385 ;
     RECT  10.26 34.385 12.618 34.493 ;
     RECT  10.515 34.493 12.618 34.591 ;
     RECT  13.644 33.581 14.238 34.591 ;
     RECT  10.515 34.591 14.238 34.637 ;
     RECT  2.304 34.349 8.838 34.655 ;
     RECT  13.68 34.637 14.238 35.035 ;
     RECT  9.72 35.509 9.738 35.699 ;
     RECT  3.996 34.655 8.838 35.815 ;
     RECT  10.515 34.637 12.654 35.851 ;
     RECT  13.68 35.035 14.958 35.899 ;
     RECT  3.996 35.815 8.874 35.969 ;
     RECT  9.828 35.851 12.654 35.969 ;
     RECT  2.304 34.655 3.258 35.977 ;
     RECT  3.996 35.969 8.838 35.977 ;
     RECT  13.644 35.899 14.958 36.149 ;
     RECT  2.304 35.977 8.838 36.509 ;
     RECT  10.26 35.969 12.654 36.523 ;
     RECT  13.644 36.149 14.238 36.523 ;
     RECT  10.26 36.523 14.238 36.617 ;
     RECT  13.68 36.617 14.238 36.749 ;
     RECT  10.26 36.617 12.582 36.931 ;
     RECT  7.668 36.509 8.838 37.021 ;
     RECT  10.224 36.931 12.582 37.021 ;
     RECT  13.752 36.749 14.238 37.049 ;
     RECT  7.668 37.021 12.582 37.085 ;
     RECT  2.304 36.509 6.894 37.435 ;
     RECT  7.668 37.085 12.402 37.435 ;
     RECT  13.752 37.049 13.77 37.561 ;
     RECT  2.304 37.435 12.402 37.589 ;
     RECT  13.644 37.561 13.77 37.613 ;
     RECT  9.54 37.589 12.402 37.625 ;
     RECT  2.304 37.589 8.586 37.771 ;
     RECT  14.94 37.339 14.958 37.771 ;
     RECT  11.628 37.625 12.402 37.831 ;
     RECT  9.54 37.625 10.797 37.859 ;
     RECT  2.268 37.771 8.586 38.003 ;
     RECT  11.628 37.831 12.618 38.101 ;
     RECT  2.304 38.003 8.586 38.165 ;
     RECT  11.628 38.101 12.762 38.201 ;
     RECT  14.184 37.771 14.958 38.395 ;
     RECT  6.84 38.165 8.586 38.515 ;
     RECT  10.26 37.859 10.797 38.515 ;
     RECT  11.628 38.201 12.618 38.515 ;
     RECT  10.26 38.515 12.618 38.579 ;
     RECT  13.644 38.395 14.958 38.579 ;
     RECT  6.84 38.515 8.874 38.641 ;
     RECT  6.84 38.641 8.946 38.741 ;
     RECT  0.144 38.137 0.162 38.765 ;
     RECT  2.304 38.165 5.814 39.055 ;
     RECT  6.84 38.741 8.838 39.055 ;
     RECT  10.404 38.579 12.618 39.209 ;
     RECT  14.22 38.579 14.958 39.293 ;
     RECT  10.515 39.209 12.618 39.865 ;
     RECT  14.22 39.293 14.238 39.883 ;
     RECT  10.515 39.865 12.654 40.019 ;
     RECT  13.644 39.883 14.238 40.091 ;
     RECT  2.304 39.055 8.838 40.135 ;
     RECT  2.304 40.135 8.874 40.171 ;
     RECT  10.515 40.019 12.474 40.171 ;
     RECT  2.304 40.171 9.306 40.289 ;
     RECT  14.22 40.091 14.238 40.315 ;
     RECT  14.22 40.315 14.958 40.361 ;
     RECT  10.476 40.171 12.474 40.631 ;
     RECT  10.515 40.631 12.474 40.801 ;
     RECT  9.54 40.711 9.558 40.829 ;
     RECT  14.22 40.361 14.238 40.873 ;
     RECT  10.515 40.801 12.69 40.901 ;
     RECT  13.68 40.873 14.238 41.179 ;
     RECT  2.304 40.289 8.802 41.369 ;
     RECT  4.032 41.369 8.802 41.755 ;
     RECT  4.032 41.755 8.838 42.331 ;
     RECT  3.96 42.331 8.838 42.457 ;
     RECT  2.304 41.369 3.222 42.601 ;
     RECT  3.96 42.457 8.874 42.601 ;
     RECT  10.515 40.901 12.618 42.601 ;
     RECT  13.644 41.179 14.238 42.719 ;
     RECT  10.26 42.601 12.618 42.859 ;
     RECT  10.26 42.859 13.086 42.989 ;
     RECT  2.304 42.601 8.874 42.997 ;
     RECT  10.296 42.989 13.086 43.061 ;
     RECT  2.304 42.997 9.234 43.169 ;
     RECT  14.22 42.719 14.238 43.483 ;
     RECT  2.304 43.169 9.162 43.529 ;
     RECT  13.644 43.483 14.238 43.601 ;
     RECT  13.68 43.601 14.238 43.681 ;
     RECT  10.296 43.061 12.654 43.771 ;
     RECT  10.26 43.771 12.654 44.041 ;
     RECT  10.26 44.041 12.69 44.113 ;
     RECT  10.08 44.113 12.69 44.141 ;
     RECT  10.08 44.141 12.654 44.213 ;
     RECT  13.68 43.681 14.958 44.381 ;
     RECT  10.224 44.213 12.654 44.609 ;
     RECT  0.144 43.723 0.162 44.669 ;
     RECT  10.26 44.609 12.654 44.879 ;
     RECT  13.68 44.381 13.698 44.923 ;
     RECT  2.304 43.529 8.838 44.995 ;
     RECT  2.304 44.995 9.378 45.149 ;
     RECT  13.644 44.923 13.698 45.211 ;
     RECT  14.94 44.381 14.958 45.211 ;
     RECT  10.515 44.879 12.654 45.329 ;
     RECT  13.644 45.211 14.958 45.491 ;
     RECT  10.515 45.329 11.286 45.805 ;
     RECT  0.216 45.835 0.234 46.013 ;
     RECT  2.304 45.149 8.838 46.075 ;
     RECT  10.404 45.805 11.286 46.111 ;
     RECT  12.06 45.329 12.654 46.111 ;
     RECT  2.304 46.075 8.874 46.229 ;
     RECT  10.404 46.111 12.654 46.229 ;
     RECT  14.22 45.491 14.958 46.267 ;
     RECT  13.644 46.267 14.958 46.459 ;
     RECT  10.515 46.229 12.654 46.769 ;
     RECT  13.536 46.459 14.958 46.795 ;
     RECT  13.536 46.795 15.102 46.841 ;
     RECT  13.644 46.841 15.102 46.925 ;
     RECT  15.084 46.925 15.102 47.117 ;
     RECT  2.304 46.229 8.838 47.281 ;
     RECT  2.304 47.281 9.378 47.579 ;
     RECT  13.644 46.925 14.238 47.651 ;
     RECT  2.304 47.579 8.874 47.849 ;
     RECT  13.68 47.651 14.238 48.173 ;
     RECT  10.515 46.769 12.618 48.199 ;
     RECT  10.515 48.199 12.654 48.271 ;
     RECT  9.864 48.271 12.654 48.361 ;
     RECT  9.684 48.361 12.654 48.389 ;
     RECT  14.22 48.173 14.238 48.433 ;
     RECT  14.22 48.433 14.958 48.605 ;
     RECT  9.684 48.389 9.702 48.659 ;
     RECT  14.22 48.605 14.274 49.195 ;
     RECT  2.304 47.849 8.838 49.315 ;
     RECT  2.304 49.315 8.874 49.351 ;
     RECT  10.515 48.389 12.654 49.441 ;
     RECT  2.304 49.351 9.306 49.469 ;
     RECT  14.184 49.195 14.274 49.513 ;
     RECT  10.515 49.441 12.69 49.541 ;
     RECT  10.515 49.541 12.618 49.621 ;
     RECT  13.68 49.513 14.274 49.627 ;
     RECT  10.188 49.621 12.618 49.891 ;
     RECT  10.116 49.891 12.618 49.981 ;
     RECT  13.68 49.627 14.958 50.093 ;
     RECT  9.684 49.981 12.618 50.279 ;
     RECT  2.304 49.469 8.838 50.315 ;
     RECT  14.184 50.093 14.958 50.525 ;
     RECT  10.188 50.279 12.618 50.549 ;
     RECT  0.144 50.491 0.162 50.621 ;
     RECT  14.22 50.525 14.958 51.089 ;
     RECT  2.304 50.315 8.586 51.097 ;
     RECT  14.22 51.089 14.922 51.355 ;
     RECT  10.26 50.549 12.618 51.359 ;
     RECT  2.304 51.097 8.838 51.395 ;
     RECT  13.644 51.355 14.922 51.629 ;
     RECT  2.412 51.395 8.838 51.665 ;
     RECT  2.415 51.665 8.838 52.015 ;
     RECT  2.415 52.015 8.874 52.051 ;
     RECT  2.415 52.051 9.306 52.411 ;
     RECT  13.644 51.629 14.274 52.445 ;
     RECT  10.404 51.359 12.618 52.591 ;
     RECT  13.644 52.445 13.662 52.637 ;
     RECT  10.26 52.591 12.618 52.825 ;
     RECT  2.304 52.411 9.306 52.979 ;
     RECT  14.904 52.861 14.922 52.987 ;
     RECT  10.26 52.825 12.654 53.221 ;
     RECT  14.904 52.987 14.958 53.221 ;
     RECT  10.26 53.221 12.69 53.249 ;
     RECT  14.22 53.221 14.958 53.261 ;
     RECT  10.515 53.249 12.69 53.293 ;
     RECT  10.515 53.293 13.122 53.501 ;
     RECT  0.144 53.467 0.162 53.597 ;
     RECT  14.904 53.261 14.958 53.693 ;
     RECT  9.684 53.401 9.774 54.211 ;
     RECT  10.515 53.501 12.762 54.211 ;
     RECT  9.684 54.211 12.762 54.329 ;
     RECT  2.304 52.979 8.874 54.365 ;
     RECT  6.804 54.365 8.874 54.481 ;
     RECT  9.684 54.329 9.774 54.481 ;
     RECT  13.644 54.091 13.662 54.523 ;
     RECT  14.94 53.693 14.958 54.523 ;
     RECT  10.515 54.329 12.762 54.571 ;
     RECT  6.804 54.481 9.774 54.599 ;
     RECT  2.304 54.365 6.03 54.635 ;
     RECT  10.515 54.571 12.906 54.671 ;
     RECT  13.644 54.523 14.958 54.749 ;
     RECT  9.612 54.599 9.774 55.139 ;
     RECT  9.612 55.139 9.63 55.211 ;
     RECT  2.34 54.635 6.03 55.243 ;
     RECT  6.804 54.599 8.874 55.243 ;
     RECT  2.34 55.243 8.874 55.409 ;
     RECT  13.644 54.749 14.238 55.481 ;
     RECT  13.68 55.481 14.238 55.613 ;
     RECT  0.144 55.255 0.162 55.709 ;
     RECT  2.34 55.409 8.838 55.771 ;
     RECT  10.515 54.671 12.654 55.859 ;
     RECT  14.22 55.613 14.238 55.957 ;
     RECT  10.515 55.859 12.618 56.129 ;
     RECT  14.22 55.957 14.274 56.635 ;
     RECT  0.216 56.635 0.234 56.813 ;
     RECT  10.515 56.129 11.718 56.875 ;
     RECT  12.456 56.129 12.618 56.875 ;
     RECT  2.304 55.771 8.838 56.911 ;
     RECT  10.515 56.875 12.654 57.029 ;
     RECT  2.304 56.911 8.874 57.065 ;
     RECT  13.644 56.635 14.274 57.101 ;
     RECT  13.644 57.101 14.238 57.299 ;
     RECT  10.515 57.029 12.618 57.451 ;
     RECT  2.304 57.065 8.586 57.955 ;
     RECT  10.224 57.451 12.618 58.109 ;
     RECT  13.644 57.299 13.95 58.123 ;
     RECT  2.304 57.955 8.946 58.145 ;
     RECT  10.224 58.109 12.582 58.415 ;
     RECT  13.644 58.123 14.238 58.555 ;
     RECT  10.224 58.415 12.546 58.693 ;
     RECT  13.608 58.555 14.238 58.939 ;
     RECT  2.304 58.145 8.91 58.955 ;
     RECT  2.304 58.955 8.874 59.063 ;
     RECT  13.608 58.939 14.958 59.099 ;
     RECT  2.304 59.063 6.858 59.189 ;
     RECT  7.596 59.063 8.874 59.189 ;
     RECT  14.22 59.099 14.958 59.189 ;
     RECT  4.572 59.189 6.858 59.225 ;
     RECT  10.008 58.693 12.546 59.233 ;
     RECT  2.304 59.189 3.69 59.261 ;
     RECT  4.572 59.225 6.03 59.459 ;
     RECT  4.572 59.459 5.778 59.729 ;
     RECT  7.815 59.189 8.874 59.729 ;
     RECT  10.008 59.233 12.618 59.729 ;
     RECT  5.115 59.729 5.778 59.765 ;
     RECT  6.768 59.225 6.858 59.837 ;
     RECT  10.515 59.729 12.618 59.999 ;
     RECT  2.304 59.261 3.618 60.269 ;
     RECT  10.515 59.999 12.51 60.269 ;
     RECT  14.868 59.189 14.958 60.269 ;
     RECT  11.736 60.269 12.51 60.305 ;
     RECT  2.304 60.269 3.078 60.539 ;
     RECT  14.868 60.269 14.922 60.539 ;
     RECT  2.304 60.539 2.697 60.575 ;
     RECT  11.844 60.305 12.51 60.575 ;
     RECT  11.844 60.575 11.862 60.809 ;
     RECT  14.868 60.539 14.886 60.809 ;
     RECT  2.415 60.575 2.697 62.387 ;
     RECT  5.115 59.765 5.397 62.387 ;
     RECT  7.815 59.729 8.097 62.387 ;
     RECT  10.515 60.269 10.797 62.387 ;
     RECT  2.415 62.387 2.505 62.657 ;
     RECT  5.115 62.387 5.205 62.657 ;
     RECT  7.815 62.387 7.905 62.657 ;
     RECT  10.515 62.387 10.605 62.657 ;
    LAYER M4 ;
     RECT  0.085 1.392 0.108 1.416 ;
     RECT  0.085 29.856 0.108 29.88 ;
     RECT  0.108 5.424 0.173 59.4 ;
     RECT  0.173 5.616 2.408 59.4 ;
     RECT  2.408 2.148 2.512 62.652 ;
     RECT  2.512 2.418 2.704 62.382 ;
     RECT  2.704 28.464 2.765 30.168 ;
     RECT  2.704 31.2 2.765 32.232 ;
     RECT  2.704 47.328 2.765 48.168 ;
     RECT  2.704 50.592 2.765 55.704 ;
     RECT  2.704 58.128 2.765 59.208 ;
     RECT  2.704 9.504 2.801 10.728 ;
     RECT  2.704 42.24 2.801 46.008 ;
     RECT  2.765 59.184 2.801 59.208 ;
     RECT  2.704 11.76 2.837 11.976 ;
     RECT  2.704 13.632 2.837 13.656 ;
     RECT  2.704 18.72 2.837 23.4 ;
     RECT  2.704 37.344 2.837 37.368 ;
     RECT  2.801 42.24 2.837 42.264 ;
     RECT  2.801 43.296 2.837 46.008 ;
     RECT  2.765 47.328 2.837 47.352 ;
     RECT  2.801 9.504 2.873 10.152 ;
     RECT  2.765 29.52 2.873 30.168 ;
     RECT  2.704 33.552 2.873 34.2 ;
     RECT  2.704 38.736 2.909 40.344 ;
     RECT  2.704 16.896 2.981 17.688 ;
     RECT  2.765 58.128 2.981 58.152 ;
     RECT  2.704 35.232 3.017 35.976 ;
     RECT  2.873 10.128 3.089 10.152 ;
     RECT  2.837 19.248 3.089 23.4 ;
     RECT  2.873 29.856 3.089 30.168 ;
     RECT  2.765 53.568 3.089 55.704 ;
     RECT  2.909 38.736 3.125 39.528 ;
     RECT  2.765 31.68 3.197 32.232 ;
     RECT  2.704 6 3.305 6.168 ;
     RECT  2.704 15.264 3.305 15.288 ;
     RECT  3.089 55.68 3.305 55.704 ;
     RECT  2.704 7.2 3.443 7.416 ;
     RECT  2.765 50.592 3.443 52.152 ;
     RECT  3.089 20.976 3.449 23.4 ;
     RECT  2.837 43.824 3.449 46.008 ;
     RECT  3.305 6.144 3.484 6.168 ;
     RECT  3.443 7.392 3.521 7.416 ;
     RECT  2.837 11.76 3.521 11.784 ;
     RECT  2.981 16.896 3.521 16.92 ;
     RECT  3.089 19.248 3.521 19.368 ;
     RECT  3.449 23.376 3.521 23.4 ;
     RECT  2.765 28.464 3.521 28.488 ;
     RECT  3.089 53.568 3.521 54.12 ;
     RECT  2.704 26.064 3.557 27.096 ;
     RECT  2.704 56.784 3.557 56.808 ;
     RECT  2.704 8.448 3.629 8.52 ;
     RECT  3.449 20.976 3.629 22.248 ;
     RECT  3.197 31.68 3.629 31.704 ;
     RECT  3.125 39.504 3.665 39.528 ;
     RECT  3.449 44.64 3.665 46.008 ;
     RECT  3.443 50.592 3.665 51.384 ;
     RECT  3.521 53.568 3.665 53.592 ;
     RECT  3.017 35.952 4.028 35.976 ;
     RECT  4.028 35.952 4.115 36.456 ;
     RECT  2.873 33.552 4.201 33.576 ;
     RECT  4.069 41.136 4.46 41.16 ;
     RECT  4.46 40.992 4.501 41.16 ;
     RECT  3.665 45.504 4.597 46.008 ;
     RECT  3.089 29.856 4.705 29.88 ;
     RECT  4.273 10.176 4.769 10.2 ;
     RECT  3.629 8.496 4.789 8.52 ;
     RECT  4.769 10.176 4.789 10.872 ;
     RECT  4.501 40.992 4.796 41.688 ;
     RECT  4.796 40.56 4.813 41.688 ;
     RECT  3.665 51.36 4.813 51.384 ;
     RECT  4.789 7.968 5.108 10.872 ;
     RECT  3.629 21.12 5.108 22.248 ;
     RECT  2.704 24.912 5.108 24.936 ;
     RECT  3.557 26.832 5.108 26.856 ;
     RECT  4.705 29.856 5.108 30.36 ;
     RECT  4.201 33.552 5.108 34.392 ;
     RECT  4.115 35.952 5.108 35.976 ;
     RECT  4.796 38.736 5.108 39.528 ;
     RECT  4.813 40.56 5.108 42.312 ;
     RECT  4.597 45.504 5.108 46.296 ;
     RECT  3.925 48.432 5.108 48.456 ;
     RECT  4.813 50.688 5.108 51.384 ;
     RECT  3.913 52.464 5.108 52.488 ;
     RECT  5.108 2.148 5.212 62.652 ;
     RECT  5.212 2.418 5.404 62.382 ;
     RECT  5.404 26.496 5.609 26.856 ;
     RECT  5.404 40.8 5.617 42.312 ;
     RECT  5.404 33.552 6.221 34.392 ;
     RECT  5.404 8.496 6.323 8.52 ;
     RECT  5.404 29.856 6.365 30.36 ;
     RECT  5.404 21.12 6.38 21.144 ;
     RECT  5.404 22.176 6.38 22.248 ;
     RECT  5.404 54.384 6.38 54.408 ;
     RECT  5.404 10.56 6.397 10.584 ;
     RECT  6.38 21.12 6.397 22.248 ;
     RECT  6.365 29.856 6.397 30.264 ;
     RECT  5.404 15.408 6.437 15.432 ;
     RECT  5.617 41.136 6.437 42.312 ;
     RECT  5.404 44.976 6.437 46.632 ;
     RECT  6.397 21.12 6.467 22.824 ;
     RECT  6.38 53.28 6.467 53.304 ;
     RECT  6.38 54.384 6.467 55.944 ;
     RECT  5.404 47.856 6.473 48.456 ;
     RECT  6.467 22.176 6.481 22.824 ;
     RECT  5.404 18.72 6.509 18.744 ;
     RECT  6.397 29.808 6.517 30.264 ;
     RECT  5.404 16.416 6.563 16.44 ;
     RECT  5.404 19.92 6.563 19.944 ;
     RECT  6.467 21.12 6.563 21.144 ;
     RECT  6.473 48.432 6.563 48.456 ;
     RECT  6.437 41.136 6.805 41.64 ;
     RECT  7.148 2.832 7.808 2.856 ;
     RECT  7.189 3.984 7.808 4.44 ;
     RECT  6.397 10.56 7.808 10.776 ;
     RECT  6.481 22.176 7.808 22.2 ;
     RECT  5.404 24.912 7.808 24.936 ;
     RECT  5.609 26.496 7.808 26.52 ;
     RECT  6.517 29.088 7.808 30.264 ;
     RECT  6.221 33.552 7.808 34.104 ;
     RECT  6.805 40.896 7.808 41.64 ;
     RECT  6.437 45.936 7.808 46.536 ;
     RECT  7.808 2.148 7.912 62.652 ;
     RECT  7.912 2.418 8.104 62.382 ;
     RECT  8.104 11.136 8.165 11.16 ;
     RECT  8.104 13.824 8.165 13.848 ;
     RECT  8.104 28.944 8.165 28.968 ;
     RECT  8.104 58.656 8.165 58.68 ;
     RECT  8.104 24.912 8.201 24.936 ;
     RECT  8.104 31.68 8.201 36.552 ;
     RECT  8.104 40.896 8.237 41.736 ;
     RECT  8.104 6.096 8.243 6.12 ;
     RECT  8.104 17.088 8.243 17.688 ;
     RECT  8.104 18.72 8.243 18.744 ;
     RECT  8.104 19.776 8.243 19.8 ;
     RECT  8.201 31.68 8.243 32.616 ;
     RECT  8.201 34.896 8.243 36.552 ;
     RECT  8.237 40.992 8.243 41.736 ;
     RECT  8.104 50.064 8.243 50.088 ;
     RECT  8.104 51.12 8.243 54.36 ;
     RECT  8.104 56.352 8.243 57.048 ;
     RECT  8.104 3.984 8.281 4.008 ;
     RECT  8.104 21.648 8.921 21.672 ;
     RECT  9.673 0.576 9.757 0.6 ;
     RECT  10.508 2.148 10.612 62.652 ;
     RECT  10.612 2.418 10.804 62.382 ;
     RECT  12.661 15.744 13.057 15.768 ;
     RECT  13.057 24.672 13.093 24.696 ;
     RECT  12.517 52.8 13.093 52.824 ;
     RECT  12.589 28.272 13.525 28.296 ;
     RECT  12.553 18.096 13.597 18.12 ;
     RECT  13.057 10.464 13.633 10.488 ;
     RECT  13.597 11.52 13.633 11.544 ;
     RECT  13.057 15.744 13.633 16.008 ;
     RECT  13.597 18.096 13.633 18.552 ;
     RECT  13.525 20.016 13.633 20.04 ;
     RECT  13.093 22.752 13.633 22.776 ;
     RECT  13.093 24.672 13.633 24.888 ;
     RECT  13.057 26.544 13.633 26.568 ;
     RECT  13.525 27.6 13.633 28.296 ;
     RECT  13.093 30.576 13.633 30.6 ;
     RECT  13.597 32.304 13.633 32.328 ;
     RECT  13.093 34.608 13.633 34.632 ;
     RECT  13.057 36.528 13.633 36.552 ;
     RECT  13.057 42.864 13.633 42.888 ;
     RECT  13.525 46.464 13.633 46.488 ;
     RECT  12.589 48.384 13.633 48.408 ;
     RECT  13.093 52.8 13.633 53.496 ;
     RECT  13.597 58.56 13.633 58.584 ;
     RECT  13.633 8.352 13.669 8.808 ;
     RECT  13.633 10.464 13.669 13.032 ;
     RECT  13.633 31.872 13.669 33.384 ;
     RECT  13.633 34.416 13.669 34.632 ;
     RECT  13.633 35.904 13.669 36.552 ;
     RECT  13.633 37.584 13.669 38.424 ;
     RECT  13.633 44.976 13.669 46.488 ;
     RECT  13.633 51.36 13.669 55.368 ;
     RECT  13.633 20.016 13.849 28.488 ;
     RECT  13.633 41.184 14.137 43.512 ;
     RECT  13.669 44.784 14.137 46.488 ;
     RECT  13.669 10.272 14.173 13.032 ;
     RECT  13.633 14.304 14.173 18.552 ;
     RECT  13.633 47.52 14.173 48.408 ;
     RECT  13.669 50.064 14.173 50.088 ;
     RECT  13.669 51.36 14.173 55.608 ;
     RECT  13.669 7.92 14.209 9.24 ;
     RECT  14.173 10.272 14.209 18.552 ;
     RECT  13.849 19.584 14.209 28.488 ;
     RECT  13.633 29.52 14.209 30.6 ;
     RECT  13.669 31.872 14.209 38.424 ;
     RECT  13.633 39.888 14.209 39.912 ;
     RECT  14.137 41.184 14.209 46.488 ;
     RECT  14.173 47.52 14.209 55.608 ;
     RECT  13.633 56.64 14.209 58.584 ;
     RECT  14.209 6 14.245 6.024 ;
     RECT  14.209 7.104 14.245 58.776 ;
     RECT  14.245 5.424 14.857 58.776 ;
     RECT  14.857 5.424 15.036 59.4 ;
     RECT  15.036 46.8 15.113 47.112 ;
    LAYER M5 ;
     RECT  0.192 1.285 0.216 1.381 ;
     RECT  0.096 1.381 0.216 1.427 ;
     RECT  2.4 2.137 2.52 2.151 ;
     RECT  5.1 2.137 5.22 2.151 ;
     RECT  7.8 2.137 7.92 2.151 ;
     RECT  10.5 2.137 10.62 2.151 ;
     RECT  7.8 2.151 8.112 2.821 ;
     RECT  7.2 2.821 8.112 3.973 ;
     RECT  7.2 3.973 8.232 4.451 ;
     RECT  7.8 4.451 8.232 6.131 ;
     RECT  2.4 2.151 2.712 6.133 ;
     RECT  2.4 6.133 3.432 7.235 ;
     RECT  5.1 2.151 5.412 7.957 ;
     RECT  4.8 7.957 5.412 8.485 ;
     RECT  4.8 8.485 6.312 10.549 ;
     RECT  4.8 10.549 6.552 10.595 ;
     RECT  4.8 10.595 5.412 10.883 ;
     RECT  7.8 6.131 8.112 17.077 ;
     RECT  7.8 17.077 8.232 17.699 ;
     RECT  7.8 17.699 8.112 18.709 ;
     RECT  7.8 18.709 8.232 19.811 ;
     RECT  5.1 10.883 5.412 19.909 ;
     RECT  6.528 10.595 6.552 19.909 ;
     RECT  5.1 19.909 6.552 19.955 ;
     RECT  5.1 19.955 6.312 21.109 ;
     RECT  2.4 7.235 2.712 26.725 ;
     RECT  2.4 26.725 3.432 26.867 ;
     RECT  5.1 21.109 6.552 29.123 ;
     RECT  7.8 19.811 8.112 29.749 ;
     RECT  0.096 1.427 0.12 29.891 ;
     RECT  6.816 29.749 8.112 30.275 ;
     RECT  7.8 30.275 8.112 31.669 ;
     RECT  7.8 31.669 8.232 36.563 ;
     RECT  4.08 36.421 4.104 38.725 ;
     RECT  5.1 29.123 5.592 38.725 ;
     RECT  4.08 38.725 5.592 40.835 ;
     RECT  7.8 36.563 8.112 40.885 ;
     RECT  6.816 40.885 8.112 40.981 ;
     RECT  6.816 40.981 8.232 41.125 ;
     RECT  4.08 40.835 5.412 41.171 ;
     RECT  6.528 41.125 8.232 41.651 ;
     RECT  4.512 41.171 5.412 41.699 ;
     RECT  7.8 41.651 8.232 41.747 ;
     RECT  5.1 41.699 5.412 44.965 ;
     RECT  6.528 41.651 6.552 44.965 ;
     RECT  5.1 44.965 6.552 46.643 ;
     RECT  6.528 46.643 6.552 48.467 ;
     RECT  7.8 41.747 8.112 50.053 ;
     RECT  3.936 48.421 3.96 50.677 ;
     RECT  5.1 46.643 5.412 50.677 ;
     RECT  2.4 26.867 2.712 51.205 ;
     RECT  3.936 50.677 5.412 51.205 ;
     RECT  2.4 51.205 5.412 52.163 ;
     RECT  3.936 52.163 5.412 52.499 ;
     RECT  7.8 50.053 8.232 54.371 ;
     RECT  6.432 53.269 6.456 55.955 ;
     RECT  7.8 54.371 8.112 56.341 ;
     RECT  7.8 56.341 8.232 57.059 ;
     RECT  2.4 52.163 2.712 62.649 ;
     RECT  5.1 52.499 5.412 62.649 ;
     RECT  7.8 57.059 8.112 62.649 ;
     RECT  10.5 2.151 10.812 62.649 ;
     RECT  2.4 62.649 2.52 62.663 ;
     RECT  5.1 62.649 5.22 62.663 ;
     RECT  7.8 62.649 7.92 62.663 ;
     RECT  10.5 62.649 10.62 62.663 ;
     RECT  6.312 8.485 7.8 10.549 ;
     RECT  6.552 10.549 7.8 19.955 ;
     RECT  5.412 10.595 6.528 19.909 ;
     RECT  8.112 17.699 8.232 18.709 ;
     RECT  6.312 19.955 7.8 21.109 ;
     RECT  6.552 21.109 7.8 29.123 ;
     RECT  5.592 29.123 7.8 29.749 ;
     RECT  5.592 29.749 6.816 30.275 ;
     RECT  2.712 36.421 4.08 41.171 ;
     RECT  4.104 36.421 5.1 38.725 ;
     RECT  5.412 40.835 5.592 40.885 ;
     RECT  5.412 40.885 6.816 41.125 ;
     RECT  5.412 41.125 6.528 44.965 ;
     RECT  6.552 41.651 7.8 48.467 ;
     RECT  5.412 46.643 6.528 48.467 ;
     RECT  2.712 48.421 3.936 51.205 ;
     RECT  3.96 48.421 5.1 50.677 ;
     RECT  2.712 52.163 3.936 52.499 ;
     RECT  5.412 53.269 6.432 55.955 ;
     RECT  6.456 53.269 7.8 55.955 ;
  END
END qkh_packet_v256
END LIBRARY
